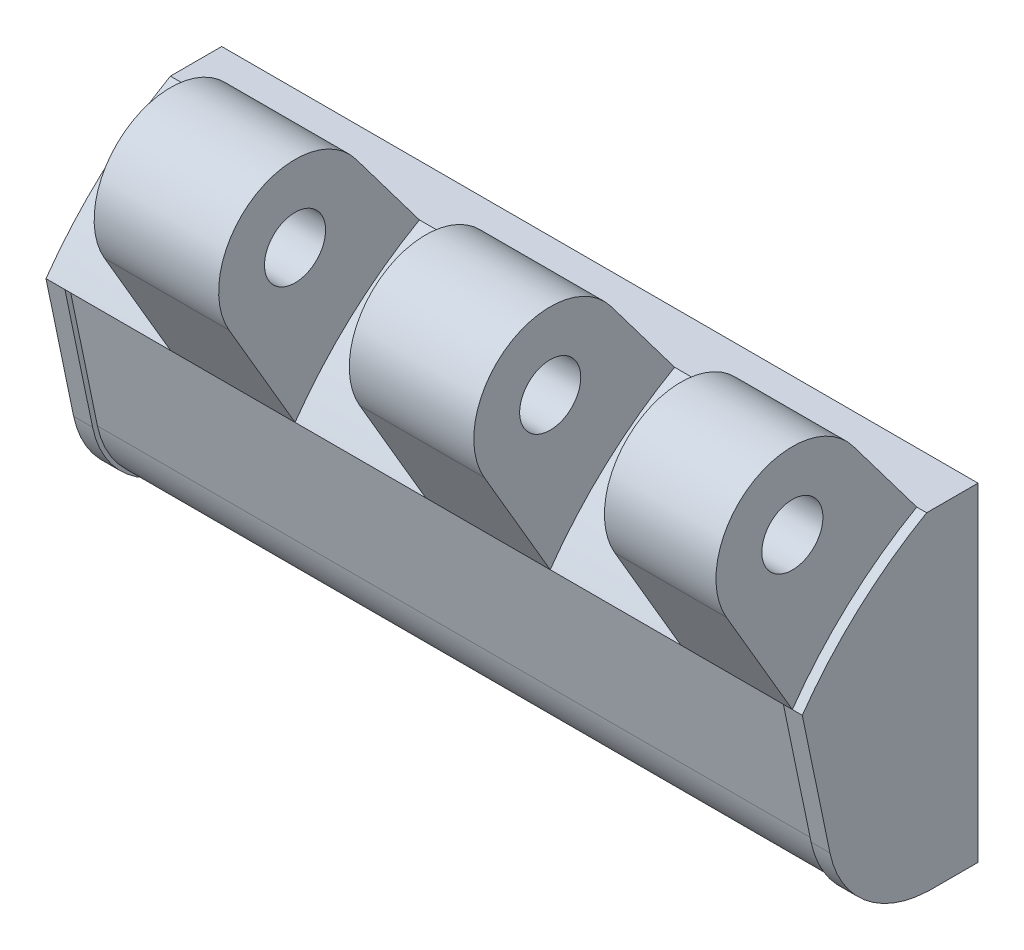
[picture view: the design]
ISO-10303-21;
HEADER;
FILE_DESCRIPTION(('STEP AP214'),'2;1');
FILE_NAME('part.step','',(''),(''),'','','');
FILE_SCHEMA(('AUTOMOTIVE_DESIGN { 1 0 10303 214 1 1 1 1 }'));
ENDSEC;
DATA;
#1=APPLICATION_CONTEXT('core data for automotive mechanical design processes');
#2=APPLICATION_PROTOCOL_DEFINITION('international standard','automotive_design',2000,#1);
#3=PRODUCT_CONTEXT('',#1,'mechanical');
#4=PRODUCT('Part','Part','',(#3));
#5=PRODUCT_RELATED_PRODUCT_CATEGORY('part','',(#4));
#6=PRODUCT_DEFINITION_FORMATION('','',#4);
#7=PRODUCT_DEFINITION_CONTEXT('part definition',#1,'design');
#8=PRODUCT_DEFINITION('design','',#6,#7);
#9=PRODUCT_DEFINITION_SHAPE('','',#8);
#10=(LENGTH_UNIT() NAMED_UNIT(*) SI_UNIT(.MILLI.,.METRE.));
#11=(NAMED_UNIT(*) PLANE_ANGLE_UNIT() SI_UNIT($,.RADIAN.));
#12=(NAMED_UNIT(*) SI_UNIT($,.STERADIAN.) SOLID_ANGLE_UNIT());
#13=UNCERTAINTY_MEASURE_WITH_UNIT(LENGTH_MEASURE(1.E-05),#10,'distance_accuracy_value','');
#14=(GEOMETRIC_REPRESENTATION_CONTEXT(3) GLOBAL_UNCERTAINTY_ASSIGNED_CONTEXT((#13)) GLOBAL_UNIT_ASSIGNED_CONTEXT((#10,
#11,#12)) REPRESENTATION_CONTEXT('',''));
#15=CARTESIAN_POINT('',(0.,0.,0.));
#16=DIRECTION('',(0.,0.,1.));
#17=DIRECTION('',(1.,0.,0.));
#18=AXIS2_PLACEMENT_3D('',#15,#16,#17);
#19=CARTESIAN_POINT('',(38.63875,-1.75,3.09));
#20=DIRECTION('',(1.,0.,0.));
#21=DIRECTION('',(0.,1.,0.));
#22=AXIS2_PLACEMENT_3D('',#19,#20,#21);
#23=CYLINDRICAL_SURFACE('',#22,5.54);
#24=CARTESIAN_POINT('',(4.3913410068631,-2.87725983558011,8.51410225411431));
#25=CARTESIAN_POINT('',(4.30887743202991,-3.00312845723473,8.48795452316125));
#26=CARTESIAN_POINT('',(4.22140014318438,-3.12482517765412,8.45808342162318));
#27=CARTESIAN_POINT('',(4.03734328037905,-3.35924431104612,8.39251775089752));
#28=CARTESIAN_POINT('',(3.94077371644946,-3.47197634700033,8.35682955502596));
#29=CARTESIAN_POINT('',(3.73932955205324,-3.68805254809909,8.28120986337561));
#30=CARTESIAN_POINT('',(3.63445953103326,-3.79140182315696,8.24128070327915));
#31=CARTESIAN_POINT('',(3.41699922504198,-3.98850366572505,8.15873930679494));
#32=CARTESIAN_POINT('',(3.30440670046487,-4.08225342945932,8.11612629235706));
#33=CARTESIAN_POINT('',(3.07245935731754,-4.25954371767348,8.02998631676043));
#34=CARTESIAN_POINT('',(2.95313025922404,-4.34311967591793,7.98646318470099));
#35=CARTESIAN_POINT('',(2.70786156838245,-4.50013603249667,7.90003043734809));
#36=CARTESIAN_POINT('',(2.58192228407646,-4.57357690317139,7.85712079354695));
#37=CARTESIAN_POINT('',(2.19444831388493,-4.77829147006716,7.73183154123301));
#38=CARTESIAN_POINT('',(1.92312321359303,-4.8940599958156,7.65283807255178));
#39=CARTESIAN_POINT('',(1.51124760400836,-5.02966399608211,7.55522317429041));
#40=CARTESIAN_POINT('',(1.3786690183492,-5.06763921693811,7.52695454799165));
#41=CARTESIAN_POINT('',(1.10976726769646,-5.13322765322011,7.47714785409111));
#42=CARTESIAN_POINT('',(0.973446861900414,-5.16084829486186,7.45560496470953));
#43=CARTESIAN_POINT('',(0.698338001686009,-5.20520859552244,7.42058171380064));
#44=CARTESIAN_POINT('',(0.55955584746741,-5.22197279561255,7.40708317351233));
#45=CARTESIAN_POINT('',(0.280513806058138,-5.24436768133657,7.38897743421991));
#46=CARTESIAN_POINT('',(0.140254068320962,-5.24999948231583,7.38436934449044));
#47=CARTESIAN_POINT('',(-0.132891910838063,-5.25000049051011,7.38436751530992));
#48=CARTESIAN_POINT('',(-0.265778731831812,-5.24494537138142,7.38850279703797));
#49=CARTESIAN_POINT('',(-0.530289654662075,-5.22483376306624,7.40477641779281));
#50=CARTESIAN_POINT('',(-0.661913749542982,-5.20977721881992,7.41691480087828));
#51=CARTESIAN_POINT('',(-0.922970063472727,-5.16992139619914,7.44848369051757));
#52=CARTESIAN_POINT('',(-1.05239890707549,-5.14510832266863,7.46792452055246));
#53=CARTESIAN_POINT('',(-1.30802798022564,-5.08613719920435,7.51302620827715));
#54=CARTESIAN_POINT('',(-1.43422653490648,-5.05197440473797,7.53869022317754));
#55=CARTESIAN_POINT('',(-1.80432713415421,-4.93691666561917,7.62256199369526));
#56=CARTESIAN_POINT('',(-2.04262731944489,-4.84299524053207,7.68804908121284));
#57=CARTESIAN_POINT('',(-2.50094454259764,-4.62304696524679,7.82858523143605));
#58=CARTESIAN_POINT('',(-2.72094186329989,-4.49698607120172,7.9036443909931));
#59=CARTESIAN_POINT('',(-3.05158525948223,-4.2745245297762,8.02223198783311));
#60=CARTESIAN_POINT('',(-3.16911911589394,-4.18813745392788,8.06566603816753));
#61=CARTESIAN_POINT('',(-3.39697526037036,-4.00554332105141,8.15105458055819));
#62=CARTESIAN_POINT('',(-3.50729551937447,-3.9093335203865,8.19300865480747));
#63=CARTESIAN_POINT('',(-3.71980166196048,-3.70769125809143,8.27370641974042));
#64=CARTESIAN_POINT('',(-3.82200921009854,-3.60228505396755,8.31245867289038));
#65=CARTESIAN_POINT('',(-4.01788726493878,-3.38241417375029,8.38530113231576));
#66=CARTESIAN_POINT('',(-4.11156457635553,-3.26795685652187,8.41939506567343));
#67=CARTESIAN_POINT('',(-4.23369002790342,-3.1050637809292,8.46191680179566));
#68=CARTESIAN_POINT('',(-4.2661655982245,-3.06029424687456,8.4730195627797));
#69=CARTESIAN_POINT('',(-4.32976870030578,-2.96962395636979,8.49428380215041));
#70=CARTESIAN_POINT('',(-4.36089689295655,-2.923723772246,8.50444574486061));
#71=CARTESIAN_POINT('',(-4.39134100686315,-2.87725983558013,8.5141022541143));
#72=B_SPLINE_CURVE_WITH_KNOTS('',3,(#24,#25,#26,#27,#28,#29,#30,#31,#32,#33,#34,#35,#36,#37,#38,
#39,#40,#41,#42,#43,#44,#45,#46,#47,#48,#49,#50,#51,#52,#53,#54,#55,#56,#57,#58,#59,#60,#61,#62,
#63,#64,#65,#66,#67,#68,#69,#70,#71),.UNSPECIFIED.,.F.,.F.,(4,2,2,2,2,2,2,2,2,2,2,2,2,2,2,2,2,2,
2,2,2,2,2,4),(0.,0.457875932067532,0.915253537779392,1.37238053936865,1.82964067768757,
2.28525969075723,2.74085746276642,3.65152617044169,4.07341460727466,4.49499988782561,
4.91562881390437,5.33621559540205,5.73472511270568,6.13323682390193,6.5323140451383,
6.93159415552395,7.72139795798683,8.51204186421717,8.96820328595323,9.42449247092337,
9.8795190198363,10.334179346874,10.5033853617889,10.6725074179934),.UNSPECIFIED.);
#73=CARTESIAN_POINT('',(4.3913410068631,-2.8772598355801,8.51410225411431));
#74=VERTEX_POINT('',#73);
#75=CARTESIAN_POINT('',(-4.3913410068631,-2.8772598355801,8.51410225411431));
#76=VERTEX_POINT('',#75);
#77=EDGE_CURVE('E438',#74,#76,#72,.T.);
#78=ORIENTED_EDGE('',*,*,#77,.T.);
#79=DIRECTION('',(1.,0.,0.));
#80=VECTOR('',#79,1.);
#81=CARTESIAN_POINT('',(38.63875,-2.8772598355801,8.51410225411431));
#82=LINE('',#81,#80);
#83=EDGE_CURVE('E304',#74,#76,#82,.F.);
#84=ORIENTED_EDGE('',*,*,#83,.F.);
#85=EDGE_LOOP('',(#78,#84));
#86=FACE_BOUND('',#85,.T.);
#87=ADVANCED_FACE('F14',(#86),#23,.F.);
#88=CARTESIAN_POINT('',(38.63875,-2.8772598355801,8.51410225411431));
#89=DIRECTION('',(0.,0.203476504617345,-0.979079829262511));
#90=DIRECTION('',(0.,0.979079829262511,0.203476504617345));
#91=AXIS2_PLACEMENT_3D('',#88,#89,#90);
#92=PLANE('',#91);
#93=CARTESIAN_POINT('',(0.,0.,9.11206654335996));
#94=DIRECTION('',(0.,0.203476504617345,-0.979079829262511));
#95=DIRECTION('',(0.,-0.979079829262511,-0.203476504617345));
#96=AXIS2_PLACEMENT_3D('',#93,#94,#95);
#97=ELLIPSE('',#96,5.36217767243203,5.25);
#98=EDGE_CURVE('E445',#76,#74,#97,.T.);
#99=ORIENTED_EDGE('',*,*,#98,.T.);
#100=ORIENTED_EDGE('',*,*,#83,.T.);
#101=EDGE_LOOP('',(#99,#100));
#102=FACE_BOUND('',#101,.T.);
#103=ADVANCED_FACE('F16',(#102),#92,.T.);
#104=CARTESIAN_POINT('',(38.63875,-1.75,3.09));
#105=DIRECTION('',(1.,0.,0.));
#106=DIRECTION('',(0.,1.,0.));
#107=AXIS2_PLACEMENT_3D('',#104,#105,#106);
#108=CYLINDRICAL_SURFACE('',#107,5.54);
#109=CARTESIAN_POINT('',(34.8913410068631,-2.87725983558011,8.51410225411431));
#110=CARTESIAN_POINT('',(34.8088774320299,-3.00312845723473,8.48795452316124));
#111=CARTESIAN_POINT('',(34.7214001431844,-3.12482517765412,8.45808342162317));
#112=CARTESIAN_POINT('',(34.537343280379,-3.35924431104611,8.39251775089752));
#113=CARTESIAN_POINT('',(34.4407737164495,-3.47197634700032,8.35682955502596));
#114=CARTESIAN_POINT('',(34.2393295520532,-3.68805254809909,8.28120986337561));
#115=CARTESIAN_POINT('',(34.1344595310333,-3.79140182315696,8.24128070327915));
#116=CARTESIAN_POINT('',(33.916999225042,-3.98850366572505,8.15873930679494));
#117=CARTESIAN_POINT('',(33.8044067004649,-4.08225342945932,8.11612629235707));
#118=CARTESIAN_POINT('',(33.5724593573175,-4.25954371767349,8.02998631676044));
#119=CARTESIAN_POINT('',(33.453130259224,-4.34311967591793,7.98646318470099));
#120=CARTESIAN_POINT('',(33.2078615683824,-4.50013603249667,7.90003043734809));
#121=CARTESIAN_POINT('',(33.0819222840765,-4.57357690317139,7.85712079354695));
#122=CARTESIAN_POINT('',(32.6944483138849,-4.77829147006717,7.73183154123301));
#123=CARTESIAN_POINT('',(32.423123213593,-4.8940599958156,7.65283807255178));
#124=CARTESIAN_POINT('',(32.0112476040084,-5.02966399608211,7.55522317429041));
#125=CARTESIAN_POINT('',(31.8786690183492,-5.06763921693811,7.52695454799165));
#126=CARTESIAN_POINT('',(31.6097672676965,-5.1332276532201,7.47714785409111));
#127=CARTESIAN_POINT('',(31.4734468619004,-5.16084829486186,7.45560496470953));
#128=CARTESIAN_POINT('',(31.198338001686,-5.20520859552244,7.42058171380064));
#129=CARTESIAN_POINT('',(31.0595558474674,-5.22197279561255,7.40708317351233));
#130=CARTESIAN_POINT('',(30.7805138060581,-5.24436768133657,7.38897743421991));
#131=CARTESIAN_POINT('',(30.640254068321,-5.24999948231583,7.38436934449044));
#132=CARTESIAN_POINT('',(30.3671080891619,-5.25000049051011,7.38436751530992));
#133=CARTESIAN_POINT('',(30.2342212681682,-5.24494537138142,7.38850279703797));
#134=CARTESIAN_POINT('',(29.9697103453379,-5.22483376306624,7.40477641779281));
#135=CARTESIAN_POINT('',(29.838086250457,-5.20977721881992,7.41691480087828));
#136=CARTESIAN_POINT('',(29.5770299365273,-5.16992139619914,7.44848369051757));
#137=CARTESIAN_POINT('',(29.4476010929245,-5.14510832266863,7.46792452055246));
#138=CARTESIAN_POINT('',(29.1919720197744,-5.08613719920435,7.51302620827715));
#139=CARTESIAN_POINT('',(29.0657734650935,-5.05197440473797,7.53869022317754));
#140=CARTESIAN_POINT('',(28.6956728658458,-4.93691666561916,7.62256199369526));
#141=CARTESIAN_POINT('',(28.4573726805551,-4.84299524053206,7.68804908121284));
#142=CARTESIAN_POINT('',(27.9990554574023,-4.62304696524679,7.82858523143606));
#143=CARTESIAN_POINT('',(27.7790581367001,-4.49698607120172,7.90364439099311));
#144=CARTESIAN_POINT('',(27.4484147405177,-4.27452452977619,8.02223198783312));
#145=CARTESIAN_POINT('',(27.330880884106,-4.18813745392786,8.06566603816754));
#146=CARTESIAN_POINT('',(27.1030247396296,-4.00554332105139,8.15105458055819));
#147=CARTESIAN_POINT('',(26.9927044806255,-3.90933352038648,8.19300865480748));
#148=CARTESIAN_POINT('',(26.7801983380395,-3.70769125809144,8.27370641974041));
#149=CARTESIAN_POINT('',(26.6779907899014,-3.60228505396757,8.31245867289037));
#150=CARTESIAN_POINT('',(26.4821127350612,-3.3824141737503,8.38530113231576));
#151=CARTESIAN_POINT('',(26.3884354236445,-3.26795685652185,8.41939506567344));
#152=CARTESIAN_POINT('',(26.2663099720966,-3.1050637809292,8.46191680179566));
#153=CARTESIAN_POINT('',(26.2338344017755,-3.06029424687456,8.4730195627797));
#154=CARTESIAN_POINT('',(26.1702312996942,-2.96962395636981,8.4942838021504));
#155=CARTESIAN_POINT('',(26.1391031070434,-2.92372377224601,8.50444574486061));
#156=CARTESIAN_POINT('',(26.1086589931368,-2.87725983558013,8.5141022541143));
#157=B_SPLINE_CURVE_WITH_KNOTS('',3,(#109,#110,#111,#112,#113,#114,#115,#116,#117,#118,#119,
#120,#121,#122,#123,#124,#125,#126,#127,#128,#129,#130,#131,#132,#133,#134,#135,#136,#137,#138,
#139,#140,#141,#142,#143,#144,#145,#146,#147,#148,#149,#150,#151,#152,#153,#154,#155,#156),
.UNSPECIFIED.,.F.,.F.,(4,2,2,2,2,2,2,2,2,2,2,2,2,2,2,2,2,2,2,2,2,2,2,4),(0.,0.457875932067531,
0.915253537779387,1.37238053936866,1.82964067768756,2.28525969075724,2.74085746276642,
3.65152617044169,4.07341460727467,4.49499988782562,4.91562881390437,5.33621559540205,
5.73472511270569,6.13323682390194,6.53231404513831,6.93159415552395,7.72139795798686,
8.51204186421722,8.96820328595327,9.42449247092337,9.87951901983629,10.334179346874,
10.5033853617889,10.6725074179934),.UNSPECIFIED.);
#158=CARTESIAN_POINT('',(34.8913410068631,-2.8772598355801,8.51410225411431));
#159=VERTEX_POINT('',#158);
#160=CARTESIAN_POINT('',(26.1086589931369,-2.8772598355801,8.51410225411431));
#161=VERTEX_POINT('',#160);
#162=EDGE_CURVE('E409',#159,#161,#157,.T.);
#163=ORIENTED_EDGE('',*,*,#162,.T.);
#164=DIRECTION('',(1.,0.,0.));
#165=VECTOR('',#164,1.);
#166=CARTESIAN_POINT('',(38.63875,-2.8772598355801,8.51410225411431));
#167=LINE('',#166,#165);
#168=EDGE_CURVE('E301',#159,#161,#167,.F.);
#169=ORIENTED_EDGE('',*,*,#168,.F.);
#170=EDGE_LOOP('',(#163,#169));
#171=FACE_BOUND('',#170,.T.);
#172=ADVANCED_FACE('F424',(#171),#108,.F.);
#173=CARTESIAN_POINT('',(38.63875,-2.8772598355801,8.51410225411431));
#174=DIRECTION('',(0.,0.203476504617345,-0.979079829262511));
#175=DIRECTION('',(0.,0.979079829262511,0.203476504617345));
#176=AXIS2_PLACEMENT_3D('',#173,#174,#175);
#177=PLANE('',#176);
#178=CARTESIAN_POINT('',(30.5,0.,9.11206654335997));
#179=DIRECTION('',(0.,0.203476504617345,-0.979079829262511));
#180=DIRECTION('',(0.,-0.979079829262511,-0.203476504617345));
#181=AXIS2_PLACEMENT_3D('',#178,#179,#180);
#182=ELLIPSE('',#181,5.36217767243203,5.25);
#183=EDGE_CURVE('E418',#161,#159,#182,.T.);
#184=ORIENTED_EDGE('',*,*,#183,.T.);
#185=ORIENTED_EDGE('',*,*,#168,.T.);
#186=EDGE_LOOP('',(#184,#185));
#187=FACE_BOUND('',#186,.T.);
#188=ADVANCED_FACE('F429',(#187),#177,.T.);
#189=CARTESIAN_POINT('',(0.,0.,7.675));
#190=DIRECTION('',(0.,0.,-1.));
#191=DIRECTION('',(-1.,0.,0.));
#192=AXIS2_PLACEMENT_3D('',#189,#190,#191);
#193=CYLINDRICAL_SURFACE('',#192,5.25);
#194=CARTESIAN_POINT('',(0.,0.,4.99999999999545));
#195=DIRECTION('',(0.,0.,1.));
#196=DIRECTION('',(0.,1.,0.));
#197=AXIS2_PLACEMENT_3D('',#194,#195,#196);
#198=CIRCLE('',#197,5.24999999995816);
#199=CARTESIAN_POINT('',(0.,5.24999999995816,4.99999999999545));
#200=VERTEX_POINT('',#199);
#201=EDGE_CURVE('E821',#200,#200,#198,.F.);
#202=ORIENTED_EDGE('',*,*,#201,.T.);
#203=EDGE_LOOP('',(#202));
#204=FACE_BOUND('',#203,.T.);
#205=ORIENTED_EDGE('',*,*,#98,.F.);
#206=ORIENTED_EDGE('',*,*,#77,.F.);
#207=EDGE_LOOP('',(#205,#206));
#208=FACE_BOUND('',#207,.T.);
#209=ADVANCED_FACE('F433',(#204,#208),#193,.F.);
#210=CARTESIAN_POINT('',(30.5,0.,7.675));
#211=DIRECTION('',(0.,0.,-1.));
#212=DIRECTION('',(-1.,0.,0.));
#213=AXIS2_PLACEMENT_3D('',#210,#211,#212);
#214=CYLINDRICAL_SURFACE('',#213,5.25);
#215=CARTESIAN_POINT('',(30.5,0.,4.99999999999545));
#216=DIRECTION('',(0.,0.,1.));
#217=DIRECTION('',(0.,1.,0.));
#218=AXIS2_PLACEMENT_3D('',#215,#216,#217);
#219=CIRCLE('',#218,5.24999999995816);
#220=CARTESIAN_POINT('',(30.5,5.24999999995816,4.99999999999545));
#221=VERTEX_POINT('',#220);
#222=EDGE_CURVE('E804',#221,#221,#219,.F.);
#223=ORIENTED_EDGE('',*,*,#222,.T.);
#224=EDGE_LOOP('',(#223));
#225=FACE_BOUND('',#224,.T.);
#226=ORIENTED_EDGE('',*,*,#183,.F.);
#227=ORIENTED_EDGE('',*,*,#162,.F.);
#228=EDGE_LOOP('',(#226,#227));
#229=FACE_BOUND('',#228,.T.);
#230=ADVANCED_FACE('F420',(#225,#229),#214,.F.);
#231=CARTESIAN_POINT('',(0.,0.,4.99999999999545));
#232=DIRECTION('',(0.,0.,1.));
#233=DIRECTION('',(1.,0.,0.));
#234=AXIS2_PLACEMENT_3D('',#231,#232,#233);
#235=CONICAL_SURFACE('',#234,5.24999999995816,0.896055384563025);
#236=CARTESIAN_POINT('',(0.,0.,3.));
#237=DIRECTION('',(0.,0.,-1.));
#238=DIRECTION('',(-1.,0.,0.));
#239=AXIS2_PLACEMENT_3D('',#236,#237,#238);
#240=CIRCLE('',#239,2.75);
#241=CARTESIAN_POINT('',(-2.75,0.,3.));
#242=VERTEX_POINT('',#241);
#243=EDGE_CURVE('E759',#242,#242,#240,.T.);
#244=ORIENTED_EDGE('',*,*,#243,.T.);
#245=EDGE_LOOP('',(#244));
#246=FACE_BOUND('',#245,.T.);
#247=ORIENTED_EDGE('',*,*,#201,.F.);
#248=EDGE_LOOP('',(#247));
#249=FACE_BOUND('',#248,.T.);
#250=ADVANCED_FACE('F546',(#246,#249),#235,.F.);
#251=CARTESIAN_POINT('',(30.5,0.,4.99999999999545));
#252=DIRECTION('',(0.,0.,1.));
#253=DIRECTION('',(1.,0.,0.));
#254=AXIS2_PLACEMENT_3D('',#251,#252,#253);
#255=CONICAL_SURFACE('',#254,5.24999999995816,0.896055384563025);
#256=CARTESIAN_POINT('',(30.5,0.,3.));
#257=DIRECTION('',(0.,0.,-1.));
#258=DIRECTION('',(-1.,0.,0.));
#259=AXIS2_PLACEMENT_3D('',#256,#257,#258);
#260=CIRCLE('',#259,2.75);
#261=CARTESIAN_POINT('',(27.75,0.,3.));
#262=VERTEX_POINT('',#261);
#263=EDGE_CURVE('E340',#262,#262,#260,.T.);
#264=ORIENTED_EDGE('',*,*,#263,.T.);
#265=EDGE_LOOP('',(#264));
#266=FACE_BOUND('',#265,.T.);
#267=ORIENTED_EDGE('',*,*,#222,.F.);
#268=EDGE_LOOP('',(#267));
#269=FACE_BOUND('',#268,.T.);
#270=ADVANCED_FACE('F549',(#266,#269),#255,.F.);
#271=CARTESIAN_POINT('',(0.,0.,1.5));
#272=DIRECTION('',(0.,0.,-1.));
#273=DIRECTION('',(-1.,0.,0.));
#274=AXIS2_PLACEMENT_3D('',#271,#272,#273);
#275=CYLINDRICAL_SURFACE('',#274,2.75);
#276=CARTESIAN_POINT('',(0.,0.,0.));
#277=DIRECTION('',(0.,0.,-1.));
#278=DIRECTION('',(-1.,0.,0.));
#279=AXIS2_PLACEMENT_3D('',#276,#277,#278);
#280=CIRCLE('',#279,2.75);
#281=CARTESIAN_POINT('',(-2.75,0.,0.));
#282=VERTEX_POINT('',#281);
#283=EDGE_CURVE('E320',#282,#282,#280,.F.);
#284=ORIENTED_EDGE('',*,*,#283,.F.);
#285=EDGE_LOOP('',(#284));
#286=FACE_BOUND('',#285,.T.);
#287=ORIENTED_EDGE('',*,*,#243,.F.);
#288=EDGE_LOOP('',(#287));
#289=FACE_BOUND('',#288,.T.);
#290=ADVANCED_FACE('F553',(#286,#289),#275,.F.);
#291=CARTESIAN_POINT('',(30.5,0.,1.5));
#292=DIRECTION('',(0.,0.,-1.));
#293=DIRECTION('',(-1.,0.,0.));
#294=AXIS2_PLACEMENT_3D('',#291,#292,#293);
#295=CYLINDRICAL_SURFACE('',#294,2.75);
#296=CARTESIAN_POINT('',(30.5,0.,0.));
#297=DIRECTION('',(0.,0.,-1.));
#298=DIRECTION('',(-1.,0.,0.));
#299=AXIS2_PLACEMENT_3D('',#296,#297,#298);
#300=CIRCLE('',#299,2.75);
#301=CARTESIAN_POINT('',(27.75,0.,0.));
#302=VERTEX_POINT('',#301);
#303=EDGE_CURVE('E316',#302,#302,#300,.F.);
#304=ORIENTED_EDGE('',*,*,#303,.F.);
#305=EDGE_LOOP('',(#304));
#306=FACE_BOUND('',#305,.T.);
#307=ORIENTED_EDGE('',*,*,#263,.F.);
#308=EDGE_LOOP('',(#307));
#309=FACE_BOUND('',#308,.T.);
#310=ADVANCED_FACE('F603',(#306,#309),#295,.F.);
#311=CARTESIAN_POINT('',(38.7625,-1.75,3.09));
#312=DIRECTION('',(1.,0.,0.));
#313=DIRECTION('',(0.,1.,0.));
#314=AXIS2_PLACEMENT_3D('',#311,#312,#313);
#315=CYLINDRICAL_SURFACE('',#314,5.54);
#316=CARTESIAN_POINT('',(-8.2625,-1.75,3.09));
#317=DIRECTION('',(1.,0.,0.));
#318=DIRECTION('',(0.,1.,0.));
#319=AXIS2_PLACEMENT_3D('',#316,#317,#318);
#320=CIRCLE('',#319,5.54);
#321=CARTESIAN_POINT('',(-8.2625,-7.28345498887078,3.35921345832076));
#322=VERTEX_POINT('',#321);
#323=CARTESIAN_POINT('',(-8.2625,-2.8772598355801,8.51410225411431));
#324=VERTEX_POINT('',#323);
#325=EDGE_CURVE('E406',#322,#324,#320,.F.);
#326=ORIENTED_EDGE('',*,*,#325,.F.);
#327=DIRECTION('',(1.,0.,0.));
#328=VECTOR('',#327,1.);
#329=CARTESIAN_POINT('',(38.7625,-7.28345498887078,3.35921345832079));
#330=LINE('',#329,#328);
#331=CARTESIAN_POINT('',(-8.13875,-7.28345498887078,3.35921345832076));
#332=VERTEX_POINT('',#331);
#333=EDGE_CURVE('E244',#322,#332,#330,.T.);
#334=ORIENTED_EDGE('',*,*,#333,.T.);
#335=CARTESIAN_POINT('',(-8.13875,-1.75,3.09));
#336=DIRECTION('',(1.,0.,0.));
#337=DIRECTION('',(0.,1.,0.));
#338=AXIS2_PLACEMENT_3D('',#335,#336,#337);
#339=CIRCLE('',#338,5.54);
#340=CARTESIAN_POINT('',(-8.13875,-2.8772598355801,8.51410225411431));
#341=VERTEX_POINT('',#340);
#342=EDGE_CURVE('E18',#332,#341,#339,.F.);
#343=ORIENTED_EDGE('',*,*,#342,.T.);
#344=DIRECTION('',(1.,0.,0.));
#345=VECTOR('',#344,1.);
#346=CARTESIAN_POINT('',(38.7625,-2.8772598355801,8.51410225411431));
#347=LINE('',#346,#345);
#348=EDGE_CURVE('E232',#341,#324,#347,.F.);
#349=ORIENTED_EDGE('',*,*,#348,.T.);
#350=EDGE_LOOP('',(#326,#334,#343,#349));
#351=FACE_BOUND('',#350,.T.);
#352=ADVANCED_FACE('F247',(#351),#315,.T.);
#353=CARTESIAN_POINT('',(38.7625,-1.75,3.09));
#354=DIRECTION('',(1.,0.,0.));
#355=DIRECTION('',(0.,1.,0.));
#356=AXIS2_PLACEMENT_3D('',#353,#354,#355);
#357=CYLINDRICAL_SURFACE('',#356,5.54);
#358=CARTESIAN_POINT('',(38.7625,-1.75,3.09));
#359=DIRECTION('',(1.,0.,0.));
#360=DIRECTION('',(0.,1.,0.));
#361=AXIS2_PLACEMENT_3D('',#358,#359,#360);
#362=CIRCLE('',#361,5.54);
#363=CARTESIAN_POINT('',(38.7625,-7.28345498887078,3.35921345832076));
#364=VERTEX_POINT('',#363);
#365=CARTESIAN_POINT('',(38.7625,-2.8772598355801,8.51410225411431));
#366=VERTEX_POINT('',#365);
#367=EDGE_CURVE('E385',#364,#366,#362,.F.);
#368=ORIENTED_EDGE('',*,*,#367,.T.);
#369=DIRECTION('',(1.,0.,0.));
#370=VECTOR('',#369,1.);
#371=CARTESIAN_POINT('',(38.7625,-2.8772598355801,8.51410225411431));
#372=LINE('',#371,#370);
#373=CARTESIAN_POINT('',(38.63875,-2.8772598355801,8.51410225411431));
#374=VERTEX_POINT('',#373);
#375=EDGE_CURVE('E253',#366,#374,#372,.F.);
#376=ORIENTED_EDGE('',*,*,#375,.T.);
#377=CARTESIAN_POINT('',(38.63875,-1.75,3.09));
#378=DIRECTION('',(1.,0.,0.));
#379=DIRECTION('',(0.,1.,0.));
#380=AXIS2_PLACEMENT_3D('',#377,#378,#379);
#381=CIRCLE('',#380,5.54);
#382=CARTESIAN_POINT('',(38.63875,-7.28345498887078,3.35921345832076));
#383=VERTEX_POINT('',#382);
#384=EDGE_CURVE('E826',#383,#374,#381,.F.);
#385=ORIENTED_EDGE('',*,*,#384,.F.);
#386=DIRECTION('',(1.,0.,0.));
#387=VECTOR('',#386,1.);
#388=CARTESIAN_POINT('',(38.7625,-7.28345498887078,3.35921345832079));
#389=LINE('',#388,#387);
#390=EDGE_CURVE('E256',#383,#364,#389,.T.);
#391=ORIENTED_EDGE('',*,*,#390,.T.);
#392=EDGE_LOOP('',(#368,#376,#385,#391));
#393=FACE_BOUND('',#392,.T.);
#394=ADVANCED_FACE('F467',(#393),#357,.T.);
#395=CARTESIAN_POINT('',(38.63875,-1.75,3.09));
#396=DIRECTION('',(1.,0.,0.));
#397=DIRECTION('',(0.,1.,0.));
#398=AXIS2_PLACEMENT_3D('',#395,#396,#397);
#399=CYLINDRICAL_SURFACE('',#398,6.54);
#400=CARTESIAN_POINT('',(38.63875,-1.75,3.09));
#401=DIRECTION('',(1.,0.,0.));
#402=DIRECTION('',(0.,1.,0.));
#403=AXIS2_PLACEMENT_3D('',#400,#401,#402);
#404=CIRCLE('',#403,6.54);
#405=CARTESIAN_POINT('',(38.63875,-8.28445668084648,3.35921345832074));
#406=VERTEX_POINT('',#405);
#407=CARTESIAN_POINT('',(38.63875,-3.08073634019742,9.49318208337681));
#408=VERTEX_POINT('',#407);
#409=EDGE_CURVE('E377',#406,#408,#404,.F.);
#410=ORIENTED_EDGE('',*,*,#409,.T.);
#411=DIRECTION('',(1.,0.,0.));
#412=VECTOR('',#411,1.);
#413=CARTESIAN_POINT('',(38.63875,-3.08073634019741,9.49318208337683));
#414=LINE('',#413,#412);
#415=CARTESIAN_POINT('',(-8.13875,-3.08073634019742,9.49318208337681));
#416=VERTEX_POINT('',#415);
#417=EDGE_CURVE('E380',#408,#416,#414,.F.);
#418=ORIENTED_EDGE('',*,*,#417,.T.);
#419=CARTESIAN_POINT('',(-8.13875,-1.75,3.09));
#420=DIRECTION('',(1.,0.,0.));
#421=DIRECTION('',(0.,1.,0.));
#422=AXIS2_PLACEMENT_3D('',#419,#420,#421);
#423=CIRCLE('',#422,6.54);
#424=CARTESIAN_POINT('',(-8.13875,-8.28445668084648,3.35921345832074));
#425=VERTEX_POINT('',#424);
#426=EDGE_CURVE('E381',#416,#425,#423,.T.);
#427=ORIENTED_EDGE('',*,*,#426,.T.);
#428=DIRECTION('',(1.,0.,0.));
#429=VECTOR('',#428,1.);
#430=CARTESIAN_POINT('',(40.,-8.2844566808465,3.35921345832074));
#431=LINE('',#430,#429);
#432=EDGE_CURVE('E678',#406,#425,#431,.F.);
#433=ORIENTED_EDGE('',*,*,#432,.F.);
#434=EDGE_LOOP('',(#410,#418,#427,#433));
#435=FACE_BOUND('',#434,.T.);
#436=ADVANCED_FACE('F470',(#435),#399,.T.);
#437=CARTESIAN_POINT('',(40.,-1.75,3.09));
#438=DIRECTION('',(1.,0.,0.));
#439=DIRECTION('',(0.,1.,0.));
#440=AXIS2_PLACEMENT_3D('',#437,#438,#439);
#441=CYLINDRICAL_SURFACE('',#440,6.74);
#442=CARTESIAN_POINT('',(-9.5,-1.75,3.09));
#443=DIRECTION('',(1.,0.,0.));
#444=DIRECTION('',(0.,1.,0.));
#445=AXIS2_PLACEMENT_3D('',#442,#443,#444);
#446=CIRCLE('',#445,6.74);
#447=CARTESIAN_POINT('',(-9.5,-3.12143164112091,9.68899804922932));
#448=VERTEX_POINT('',#447);
#449=CARTESIAN_POINT('',(-9.5,-8.48462130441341,3.35921345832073));
#450=VERTEX_POINT('',#449);
#451=EDGE_CURVE('E333',#448,#450,#446,.T.);
#452=ORIENTED_EDGE('',*,*,#451,.T.);
#453=DIRECTION('',(1.,0.,0.));
#454=VECTOR('',#453,1.);
#455=CARTESIAN_POINT('',(40.,-8.4846213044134,3.35921345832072));
#456=LINE('',#455,#454);
#457=CARTESIAN_POINT('',(-8.2625,-8.48462130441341,3.35921345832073));
#458=VERTEX_POINT('',#457);
#459=EDGE_CURVE('E679',#458,#450,#456,.F.);
#460=ORIENTED_EDGE('',*,*,#459,.F.);
#461=CARTESIAN_POINT('',(-8.2625,-1.75,3.09));
#462=DIRECTION('',(1.,0.,0.));
#463=DIRECTION('',(0.,1.,0.));
#464=AXIS2_PLACEMENT_3D('',#461,#462,#463);
#465=CIRCLE('',#464,6.74);
#466=CARTESIAN_POINT('',(-8.2625,-3.12143164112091,9.68899804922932));
#467=VERTEX_POINT('',#466);
#468=EDGE_CURVE('E373',#458,#467,#465,.F.);
#469=ORIENTED_EDGE('',*,*,#468,.T.);
#470=DIRECTION('',(1.,0.,0.));
#471=VECTOR('',#470,1.);
#472=CARTESIAN_POINT('',(40.,-3.1214316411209,9.68899804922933));
#473=LINE('',#472,#471);
#474=EDGE_CURVE('E372',#467,#448,#473,.F.);
#475=ORIENTED_EDGE('',*,*,#474,.T.);
#476=EDGE_LOOP('',(#452,#460,#469,#475));
#477=FACE_BOUND('',#476,.T.);
#478=ADVANCED_FACE('F544',(#477),#441,.T.);
#479=CARTESIAN_POINT('',(40.,-8.5,0.));
#480=DIRECTION('',(0.,0.,-1.));
#481=DIRECTION('',(-1.,0.,0.));
#482=AXIS2_PLACEMENT_3D('',#479,#480,#481);
#483=PLANE('',#482);
#484=DIRECTION('',(0.,1.,0.));
#485=VECTOR('',#484,1.);
#486=CARTESIAN_POINT('',(40.,-8.5,0.));
#487=LINE('',#486,#485);
#488=CARTESIAN_POINT('',(40.,13.,0.));
#489=VERTEX_POINT('',#488);
#490=CARTESIAN_POINT('',(40.,-8.5,0.));
#491=VERTEX_POINT('',#490);
#492=EDGE_CURVE('E24',#489,#491,#487,.F.);
#493=ORIENTED_EDGE('',*,*,#492,.T.);
#494=DIRECTION('',(-1.,0.,0.));
#495=VECTOR('',#494,1.);
#496=CARTESIAN_POINT('',(40.,-8.5,0.));
#497=LINE('',#496,#495);
#498=CARTESIAN_POINT('',(-9.5,-8.5,0.));
#499=VERTEX_POINT('',#498);
#500=EDGE_CURVE('E9',#491,#499,#497,.T.);
#501=ORIENTED_EDGE('',*,*,#500,.T.);
#502=DIRECTION('',(0.,1.,0.));
#503=VECTOR('',#502,1.);
#504=CARTESIAN_POINT('',(-9.5,-8.5,0.));
#505=LINE('',#504,#503);
#506=CARTESIAN_POINT('',(-9.5,13.,0.));
#507=VERTEX_POINT('',#506);
#508=EDGE_CURVE('E319',#499,#507,#505,.T.);
#509=ORIENTED_EDGE('',*,*,#508,.T.);
#510=DIRECTION('',(-1.,0.,0.));
#511=VECTOR('',#510,1.);
#512=CARTESIAN_POINT('',(40.,13.,0.));
#513=LINE('',#512,#511);
#514=EDGE_CURVE('E695',#507,#489,#513,.F.);
#515=ORIENTED_EDGE('',*,*,#514,.T.);
#516=EDGE_LOOP('',(#493,#501,#509,#515));
#517=FACE_BOUND('',#516,.T.);
#518=ORIENTED_EDGE('',*,*,#303,.T.);
#519=EDGE_LOOP('',(#518));
#520=FACE_BOUND('',#519,.T.);
#521=ORIENTED_EDGE('',*,*,#283,.T.);
#522=EDGE_LOOP('',(#521));
#523=FACE_BOUND('',#522,.T.);
#524=ADVANCED_FACE('F562',(#517,#520,#523),#483,.T.);
#525=CARTESIAN_POINT('',(40.,-8.5,3.35921345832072));
#526=DIRECTION('',(0.,-1.,0.));
#527=DIRECTION('',(1.,0.,0.));
#528=AXIS2_PLACEMENT_3D('',#525,#526,#527);
#529=PLANE('',#528);
#530=DIRECTION('',(0.,0.,1.));
#531=VECTOR('',#530,1.);
#532=CARTESIAN_POINT('',(40.,-8.5,3.35921345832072));
#533=LINE('',#532,#531);
#534=CARTESIAN_POINT('',(40.,-8.5,3.35921345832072));
#535=VERTEX_POINT('',#534);
#536=EDGE_CURVE('E33',#491,#535,#533,.T.);
#537=ORIENTED_EDGE('',*,*,#536,.T.);
#538=DIRECTION('',(1.,0.,0.));
#539=VECTOR('',#538,1.);
#540=CARTESIAN_POINT('',(40.,-8.5,3.35921345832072));
#541=LINE('',#540,#539);
#542=CARTESIAN_POINT('',(-9.5,-8.5,3.35921345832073));
#543=VERTEX_POINT('',#542);
#544=EDGE_CURVE('E323',#535,#543,#541,.F.);
#545=ORIENTED_EDGE('',*,*,#544,.T.);
#546=DIRECTION('',(0.,0.,1.));
#547=VECTOR('',#546,1.);
#548=CARTESIAN_POINT('',(-9.5,-8.5,3.35921345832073));
#549=LINE('',#548,#547);
#550=EDGE_CURVE('E660',#543,#499,#549,.F.);
#551=ORIENTED_EDGE('',*,*,#550,.T.);
#552=ORIENTED_EDGE('',*,*,#500,.F.);
#553=EDGE_LOOP('',(#537,#545,#551,#552));
#554=FACE_BOUND('',#553,.T.);
#555=ADVANCED_FACE('F600',(#554),#529,.T.);
#556=CARTESIAN_POINT('',(40.,-8.4846213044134,3.35921345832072));
#557=DIRECTION('',(0.,0.,1.));
#558=DIRECTION('',(0.,-1.,0.));
#559=AXIS2_PLACEMENT_3D('',#556,#557,#558);
#560=PLANE('',#559);
#561=DIRECTION('',(0.,1.,0.));
#562=VECTOR('',#561,1.);
#563=CARTESIAN_POINT('',(38.63875,15.5,3.35921345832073));
#564=LINE('',#563,#562);
#565=EDGE_CURVE('E249',#406,#383,#564,.T.);
#566=ORIENTED_EDGE('',*,*,#565,.F.);
#567=ORIENTED_EDGE('',*,*,#432,.T.);
#568=DIRECTION('',(0.,1.,0.));
#569=VECTOR('',#568,1.);
#570=CARTESIAN_POINT('',(-8.13875,15.5,3.35921345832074));
#571=LINE('',#570,#569);
#572=EDGE_CURVE('E226',#425,#332,#571,.T.);
#573=ORIENTED_EDGE('',*,*,#572,.T.);
#574=ORIENTED_EDGE('',*,*,#333,.F.);
#575=DIRECTION('',(0.,1.,0.));
#576=VECTOR('',#575,1.);
#577=CARTESIAN_POINT('',(-8.2625,15.5,3.35921345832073));
#578=LINE('',#577,#576);
#579=EDGE_CURVE('E408',#458,#322,#578,.T.);
#580=ORIENTED_EDGE('',*,*,#579,.F.);
#581=ORIENTED_EDGE('',*,*,#459,.T.);
#582=DIRECTION('',(0.,1.,0.));
#583=VECTOR('',#582,1.);
#584=CARTESIAN_POINT('',(-9.5,15.5,3.35921345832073));
#585=LINE('',#584,#583);
#586=EDGE_CURVE('E335',#450,#543,#585,.F.);
#587=ORIENTED_EDGE('',*,*,#586,.T.);
#588=ORIENTED_EDGE('',*,*,#544,.F.);
#589=DIRECTION('',(0.,1.,0.));
#590=VECTOR('',#589,1.);
#591=CARTESIAN_POINT('',(40.,15.5,3.35921345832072));
#592=LINE('',#591,#590);
#593=CARTESIAN_POINT('',(40.,-8.48462130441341,3.35921345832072));
#594=VERTEX_POINT('',#593);
#595=EDGE_CURVE('E327',#594,#535,#592,.F.);
#596=ORIENTED_EDGE('',*,*,#595,.F.);
#597=DIRECTION('',(1.,0.,0.));
#598=VECTOR('',#597,1.);
#599=CARTESIAN_POINT('',(40.,-8.4846213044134,3.35921345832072));
#600=LINE('',#599,#598);
#601=CARTESIAN_POINT('',(38.7625,-8.48462130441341,3.35921345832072));
#602=VERTEX_POINT('',#601);
#603=EDGE_CURVE('E675',#594,#602,#600,.F.);
#604=ORIENTED_EDGE('',*,*,#603,.T.);
#605=DIRECTION('',(0.,1.,0.));
#606=VECTOR('',#605,1.);
#607=CARTESIAN_POINT('',(38.7625,15.5,3.35921345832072));
#608=LINE('',#607,#606);
#609=EDGE_CURVE('E388',#602,#364,#608,.T.);
#610=ORIENTED_EDGE('',*,*,#609,.T.);
#611=ORIENTED_EDGE('',*,*,#390,.F.);
#612=EDGE_LOOP('',(#566,#567,#573,#574,#580,#581,#587,#588,#596,#604,#610,#611));
#613=FACE_BOUND('',#612,.T.);
#614=ADVANCED_FACE('F596',(#613),#560,.T.);
#615=CARTESIAN_POINT('',(40.,-1.75,3.09));
#616=DIRECTION('',(1.,0.,0.));
#617=DIRECTION('',(0.,1.,0.));
#618=AXIS2_PLACEMENT_3D('',#615,#616,#617);
#619=CYLINDRICAL_SURFACE('',#618,6.74);
#620=CARTESIAN_POINT('',(40.,-1.75,3.09));
#621=DIRECTION('',(1.,0.,0.));
#622=DIRECTION('',(0.,1.,0.));
#623=AXIS2_PLACEMENT_3D('',#620,#621,#622);
#624=CIRCLE('',#623,6.74);
#625=CARTESIAN_POINT('',(40.,-3.12143164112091,9.68899804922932));
#626=VERTEX_POINT('',#625);
#627=EDGE_CURVE('E324',#626,#594,#624,.T.);
#628=ORIENTED_EDGE('',*,*,#627,.F.);
#629=DIRECTION('',(1.,0.,0.));
#630=VECTOR('',#629,1.);
#631=CARTESIAN_POINT('',(40.,-3.1214316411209,9.68899804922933));
#632=LINE('',#631,#630);
#633=CARTESIAN_POINT('',(38.7625,-3.12143164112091,9.68899804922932));
#634=VERTEX_POINT('',#633);
#635=EDGE_CURVE('E344',#626,#634,#632,.F.);
#636=ORIENTED_EDGE('',*,*,#635,.T.);
#637=CARTESIAN_POINT('',(38.7625,-1.75,3.09));
#638=DIRECTION('',(1.,0.,0.));
#639=DIRECTION('',(0.,1.,0.));
#640=AXIS2_PLACEMENT_3D('',#637,#638,#639);
#641=CIRCLE('',#640,6.74);
#642=EDGE_CURVE('E341',#634,#602,#641,.T.);
#643=ORIENTED_EDGE('',*,*,#642,.T.);
#644=ORIENTED_EDGE('',*,*,#603,.F.);
#645=EDGE_LOOP('',(#628,#636,#643,#644));
#646=FACE_BOUND('',#645,.T.);
#647=ADVANCED_FACE('F462',(#646),#619,.T.);
#648=CARTESIAN_POINT('',(-8.13875,15.5,0.));
#649=DIRECTION('',(1.,0.,0.));
#650=DIRECTION('',(0.,1.,0.));
#651=AXIS2_PLACEMENT_3D('',#648,#649,#650);
#652=PLANE('',#651);
#653=ORIENTED_EDGE('',*,*,#572,.F.);
#654=ORIENTED_EDGE('',*,*,#426,.F.);
#655=DIRECTION('',(0.,-0.979079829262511,-0.203476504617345));
#656=VECTOR('',#655,1.);
#657=CARTESIAN_POINT('',(-8.13875,5.5926726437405,11.2957265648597));
#658=LINE('',#657,#656);
#659=CARTESIAN_POINT('',(-8.13875,5.5926726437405,11.2957265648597));
#660=VERTEX_POINT('',#659);
#661=EDGE_CURVE('E262',#660,#416,#658,.T.);
#662=ORIENTED_EDGE('',*,*,#661,.F.);
#663=DIRECTION('',(0.,0.,1.));
#664=VECTOR('',#663,1.);
#665=CARTESIAN_POINT('',(-8.13875,5.5926726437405,10.2743593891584));
#666=LINE('',#665,#664);
#667=CARTESIAN_POINT('',(-8.13875,5.5926726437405,10.2743593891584));
#668=VERTEX_POINT('',#667);
#669=EDGE_CURVE('E252',#660,#668,#666,.F.);
#670=ORIENTED_EDGE('',*,*,#669,.T.);
#671=DIRECTION('',(0.,0.979079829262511,0.203476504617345));
#672=VECTOR('',#671,1.);
#673=CARTESIAN_POINT('',(-8.13875,-2.8772598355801,8.51410225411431));
#674=LINE('',#673,#672);
#675=EDGE_CURVE('E236',#341,#668,#674,.T.);
#676=ORIENTED_EDGE('',*,*,#675,.F.);
#677=ORIENTED_EDGE('',*,*,#342,.F.);
#678=EDGE_LOOP('',(#653,#654,#662,#670,#676,#677));
#679=FACE_BOUND('',#678,.T.);
#680=ADVANCED_FACE('F250',(#679),#652,.F.);
#681=CARTESIAN_POINT('',(38.7625,-2.8772598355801,8.51410225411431));
#682=DIRECTION('',(0.,0.203476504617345,-0.979079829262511));
#683=DIRECTION('',(0.,0.979079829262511,0.203476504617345));
#684=AXIS2_PLACEMENT_3D('',#681,#682,#683);
#685=PLANE('',#684);
#686=DIRECTION('',(1.,0.,0.));
#687=VECTOR('',#686,1.);
#688=CARTESIAN_POINT('',(38.7625,5.5926726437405,10.2743593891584));
#689=LINE('',#688,#687);
#690=CARTESIAN_POINT('',(-8.2625,5.5926726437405,10.2743593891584));
#691=VERTEX_POINT('',#690);
#692=EDGE_CURVE('E243',#691,#668,#689,.T.);
#693=ORIENTED_EDGE('',*,*,#692,.F.);
#694=DIRECTION('',(0.,0.979079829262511,0.203476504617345));
#695=VECTOR('',#694,1.);
#696=CARTESIAN_POINT('',(-8.2625,-2.8772598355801,8.51410225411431));
#697=LINE('',#696,#695);
#698=EDGE_CURVE('E239',#324,#691,#697,.T.);
#699=ORIENTED_EDGE('',*,*,#698,.F.);
#700=ORIENTED_EDGE('',*,*,#348,.F.);
#701=ORIENTED_EDGE('',*,*,#675,.T.);
#702=EDGE_LOOP('',(#693,#699,#700,#701));
#703=FACE_BOUND('',#702,.T.);
#704=ADVANCED_FACE('F234',(#703),#685,.F.);
#705=CARTESIAN_POINT('',(-8.2625,15.5,0.));
#706=DIRECTION('',(1.,0.,0.));
#707=DIRECTION('',(0.,1.,0.));
#708=AXIS2_PLACEMENT_3D('',#705,#706,#707);
#709=PLANE('',#708);
#710=ORIENTED_EDGE('',*,*,#698,.T.);
#711=DIRECTION('',(0.,0.,1.));
#712=VECTOR('',#711,1.);
#713=CARTESIAN_POINT('',(-8.2625,5.5926726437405,10.2743593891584));
#714=LINE('',#713,#712);
#715=CARTESIAN_POINT('',(-8.2625,5.59267264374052,11.5));
#716=VERTEX_POINT('',#715);
#717=EDGE_CURVE('E781',#691,#716,#714,.T.);
#718=ORIENTED_EDGE('',*,*,#717,.T.);
#719=DIRECTION('',(0.,-0.979079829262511,-0.203476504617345));
#720=VECTOR('',#719,1.);
#721=CARTESIAN_POINT('',(-8.2625,5.59267264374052,11.5));
#722=LINE('',#721,#720);
#723=EDGE_CURVE('E376',#467,#716,#722,.F.);
#724=ORIENTED_EDGE('',*,*,#723,.F.);
#725=ORIENTED_EDGE('',*,*,#468,.F.);
#726=ORIENTED_EDGE('',*,*,#579,.T.);
#727=ORIENTED_EDGE('',*,*,#325,.T.);
#728=EDGE_LOOP('',(#710,#718,#724,#725,#726,#727));
#729=FACE_BOUND('',#728,.T.);
#730=ADVANCED_FACE('F490',(#729),#709,.T.);
#731=CARTESIAN_POINT('',(38.7625,15.5,0.));
#732=DIRECTION('',(1.,0.,0.));
#733=DIRECTION('',(0.,1.,0.));
#734=AXIS2_PLACEMENT_3D('',#731,#732,#733);
#735=PLANE('',#734);
#736=DIRECTION('',(0.,0.,1.));
#737=VECTOR('',#736,1.);
#738=CARTESIAN_POINT('',(38.7625,5.5926726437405,0.));
#739=LINE('',#738,#737);
#740=CARTESIAN_POINT('',(38.7625,5.5926726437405,10.2743593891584));
#741=VERTEX_POINT('',#740);
#742=CARTESIAN_POINT('',(38.7625,5.5926726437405,11.5));
#743=VERTEX_POINT('',#742);
#744=EDGE_CURVE('E384',#741,#743,#739,.T.);
#745=ORIENTED_EDGE('',*,*,#744,.F.);
#746=DIRECTION('',(0.,0.979079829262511,0.203476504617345));
#747=VECTOR('',#746,1.);
#748=CARTESIAN_POINT('',(38.7625,-2.8772598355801,8.51410225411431));
#749=LINE('',#748,#747);
#750=EDGE_CURVE('E387',#366,#741,#749,.T.);
#751=ORIENTED_EDGE('',*,*,#750,.F.);
#752=ORIENTED_EDGE('',*,*,#367,.F.);
#753=ORIENTED_EDGE('',*,*,#609,.F.);
#754=ORIENTED_EDGE('',*,*,#642,.F.);
#755=DIRECTION('',(0.,-0.979079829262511,-0.203476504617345));
#756=VECTOR('',#755,1.);
#757=CARTESIAN_POINT('',(38.7625,5.59267264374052,11.5));
#758=LINE('',#757,#756);
#759=EDGE_CURVE('E349',#743,#634,#758,.T.);
#760=ORIENTED_EDGE('',*,*,#759,.F.);
#761=EDGE_LOOP('',(#745,#751,#752,#753,#754,#760));
#762=FACE_BOUND('',#761,.T.);
#763=ADVANCED_FACE('F465',(#762),#735,.F.);
#764=CARTESIAN_POINT('',(38.7625,-2.8772598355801,8.51410225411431));
#765=DIRECTION('',(0.,0.203476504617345,-0.979079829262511));
#766=DIRECTION('',(0.,0.979079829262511,0.203476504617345));
#767=AXIS2_PLACEMENT_3D('',#764,#765,#766);
#768=PLANE('',#767);
#769=ORIENTED_EDGE('',*,*,#375,.F.);
#770=ORIENTED_EDGE('',*,*,#750,.T.);
#771=DIRECTION('',(-1.,0.,0.));
#772=VECTOR('',#771,1.);
#773=CARTESIAN_POINT('',(38.7625,5.5926726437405,10.2743593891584));
#774=LINE('',#773,#772);
#775=CARTESIAN_POINT('',(38.63875,5.5926726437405,10.2743593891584));
#776=VERTEX_POINT('',#775);
#777=EDGE_CURVE('E269',#741,#776,#774,.T.);
#778=ORIENTED_EDGE('',*,*,#777,.T.);
#779=DIRECTION('',(0.,0.979079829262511,0.203476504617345));
#780=VECTOR('',#779,1.);
#781=CARTESIAN_POINT('',(38.63875,-2.8772598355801,8.51410225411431));
#782=LINE('',#781,#780);
#783=EDGE_CURVE('E266',#374,#776,#782,.T.);
#784=ORIENTED_EDGE('',*,*,#783,.F.);
#785=EDGE_LOOP('',(#769,#770,#778,#784));
#786=FACE_BOUND('',#785,.T.);
#787=ADVANCED_FACE('F458',(#786),#768,.F.);
#788=CARTESIAN_POINT('',(38.63875,15.5,0.));
#789=DIRECTION('',(1.,0.,0.));
#790=DIRECTION('',(0.,1.,0.));
#791=AXIS2_PLACEMENT_3D('',#788,#789,#790);
#792=PLANE('',#791);
#793=DIRECTION('',(0.,-0.979079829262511,-0.203476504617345));
#794=VECTOR('',#793,1.);
#795=CARTESIAN_POINT('',(38.63875,5.5926726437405,11.2957265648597));
#796=LINE('',#795,#794);
#797=CARTESIAN_POINT('',(38.63875,5.5926726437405,11.2957265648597));
#798=VERTEX_POINT('',#797);
#799=EDGE_CURVE('E265',#408,#798,#796,.F.);
#800=ORIENTED_EDGE('',*,*,#799,.F.);
#801=ORIENTED_EDGE('',*,*,#409,.F.);
#802=ORIENTED_EDGE('',*,*,#565,.T.);
#803=ORIENTED_EDGE('',*,*,#384,.T.);
#804=ORIENTED_EDGE('',*,*,#783,.T.);
#805=DIRECTION('',(0.,0.,1.));
#806=VECTOR('',#805,1.);
#807=CARTESIAN_POINT('',(38.63875,5.5926726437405,10.2743593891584));
#808=LINE('',#807,#806);
#809=EDGE_CURVE('E271',#776,#798,#808,.T.);
#810=ORIENTED_EDGE('',*,*,#809,.T.);
#811=EDGE_LOOP('',(#800,#801,#802,#803,#804,#810));
#812=FACE_BOUND('',#811,.T.);
#813=ADVANCED_FACE('F454',(#812),#792,.T.);
#814=CARTESIAN_POINT('',(38.63875,5.5926726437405,11.2957265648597));
#815=DIRECTION('',(0.,-0.203476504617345,0.979079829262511));
#816=DIRECTION('',(0.,-0.979079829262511,-0.203476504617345));
#817=AXIS2_PLACEMENT_3D('',#814,#815,#816);
#818=PLANE('',#817);
#819=ORIENTED_EDGE('',*,*,#799,.T.);
#820=DIRECTION('',(-1.,0.,0.));
#821=VECTOR('',#820,1.);
#822=CARTESIAN_POINT('',(38.7625,5.5926726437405,11.2957265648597));
#823=LINE('',#822,#821);
#824=EDGE_CURVE('E286',#798,#660,#823,.T.);
#825=ORIENTED_EDGE('',*,*,#824,.T.);
#826=ORIENTED_EDGE('',*,*,#661,.T.);
#827=ORIENTED_EDGE('',*,*,#417,.F.);
#828=EDGE_LOOP('',(#819,#825,#826,#827));
#829=FACE_BOUND('',#828,.T.);
#830=ADVANCED_FACE('F450',(#829),#818,.T.);
#831=CARTESIAN_POINT('',(-9.5,15.5,0.));
#832=DIRECTION('',(1.,0.,0.));
#833=DIRECTION('',(0.,1.,0.));
#834=AXIS2_PLACEMENT_3D('',#831,#832,#833);
#835=PLANE('',#834);
#836=ORIENTED_EDGE('',*,*,#508,.F.);
#837=ORIENTED_EDGE('',*,*,#550,.F.);
#838=ORIENTED_EDGE('',*,*,#586,.F.);
#839=ORIENTED_EDGE('',*,*,#451,.F.);
#840=DIRECTION('',(0.,-0.979079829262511,-0.203476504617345));
#841=VECTOR('',#840,1.);
#842=CARTESIAN_POINT('',(-9.5,5.59267264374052,11.5));
#843=LINE('',#842,#841);
#844=CARTESIAN_POINT('',(-9.5,5.59267264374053,11.5));
#845=VERTEX_POINT('',#844);
#846=EDGE_CURVE('E336',#845,#448,#843,.T.);
#847=ORIENTED_EDGE('',*,*,#846,.F.);
#848=CARTESIAN_POINT('',(-9.5,-8.8700000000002,-9.1));
#849=DIRECTION('',(1.,0.,0.));
#850=DIRECTION('',(0.,1.,0.));
#851=AXIS2_PLACEMENT_3D('',#848,#849,#850);
#852=CIRCLE('',#851,25.17);
#853=CARTESIAN_POINT('',(-9.5,13.,3.35921345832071));
#854=VERTEX_POINT('',#853);
#855=EDGE_CURVE('E337',#854,#845,#852,.T.);
#856=ORIENTED_EDGE('',*,*,#855,.F.);
#857=DIRECTION('',(0.,0.,1.));
#858=VECTOR('',#857,1.);
#859=CARTESIAN_POINT('',(-9.5,13.,0.));
#860=LINE('',#859,#858);
#861=EDGE_CURVE('E671',#507,#854,#860,.T.);
#862=ORIENTED_EDGE('',*,*,#861,.F.);
#863=EDGE_LOOP('',(#836,#837,#838,#839,#847,#856,#862));
#864=FACE_BOUND('',#863,.T.);
#865=ADVANCED_FACE('F453',(#864),#835,.F.);
#866=CARTESIAN_POINT('',(40.,5.59267264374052,11.5));
#867=DIRECTION('',(0.,-0.203476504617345,0.979079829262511));
#868=DIRECTION('',(0.,-0.979079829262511,-0.203476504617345));
#869=AXIS2_PLACEMENT_3D('',#866,#867,#868);
#870=PLANE('',#869);
#871=ORIENTED_EDGE('',*,*,#846,.T.);
#872=ORIENTED_EDGE('',*,*,#474,.F.);
#873=ORIENTED_EDGE('',*,*,#723,.T.);
#874=DIRECTION('',(1.,0.,0.));
#875=VECTOR('',#874,1.);
#876=CARTESIAN_POINT('',(40.,5.59267264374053,11.5));
#877=LINE('',#876,#875);
#878=EDGE_CURVE('E371',#845,#716,#877,.T.);
#879=ORIENTED_EDGE('',*,*,#878,.F.);
#880=EDGE_LOOP('',(#871,#872,#873,#879));
#881=FACE_BOUND('',#880,.T.);
#882=ADVANCED_FACE('F555',(#881),#870,.T.);
#883=CARTESIAN_POINT('',(40.,13.,0.));
#884=DIRECTION('',(0.,1.,0.));
#885=DIRECTION('',(-1.,0.,0.));
#886=AXIS2_PLACEMENT_3D('',#883,#884,#885);
#887=PLANE('',#886);
#888=DIRECTION('',(0.,0.,1.));
#889=VECTOR('',#888,1.);
#890=CARTESIAN_POINT('',(40.,13.,0.));
#891=LINE('',#890,#889);
#892=CARTESIAN_POINT('',(40.,13.,3.3592134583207));
#893=VERTEX_POINT('',#892);
#894=EDGE_CURVE('E332',#489,#893,#891,.T.);
#895=ORIENTED_EDGE('',*,*,#894,.F.);
#896=ORIENTED_EDGE('',*,*,#514,.F.);
#897=ORIENTED_EDGE('',*,*,#861,.T.);
#898=DIRECTION('',(-1.,0.,0.));
#899=VECTOR('',#898,1.);
#900=CARTESIAN_POINT('',(40.,13.,3.35921345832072));
#901=LINE('',#900,#899);
#902=CARTESIAN_POINT('',(-1.35,13.,3.35921345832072));
#903=VERTEX_POINT('',#902);
#904=EDGE_CURVE('E727',#854,#903,#901,.F.);
#905=ORIENTED_EDGE('',*,*,#904,.T.);
#906=DIRECTION('',(-1.,0.,0.));
#907=VECTOR('',#906,1.);
#908=CARTESIAN_POINT('',(40.,13.,3.35921345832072));
#909=LINE('',#908,#907);
#910=CARTESIAN_POINT('',(6.8,13.,3.35921345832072));
#911=VERTEX_POINT('',#910);
#912=EDGE_CURVE('E724',#903,#911,#909,.F.);
#913=ORIENTED_EDGE('',*,*,#912,.T.);
#914=DIRECTION('',(-1.,0.,0.));
#915=VECTOR('',#914,1.);
#916=CARTESIAN_POINT('',(40.,13.,3.35921345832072));
#917=LINE('',#916,#915);
#918=CARTESIAN_POINT('',(15.35,13.,3.35921345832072));
#919=VERTEX_POINT('',#918);
#920=EDGE_CURVE('E716',#911,#919,#917,.F.);
#921=ORIENTED_EDGE('',*,*,#920,.T.);
#922=DIRECTION('',(-1.,0.,0.));
#923=VECTOR('',#922,1.);
#924=CARTESIAN_POINT('',(40.,13.,3.35921345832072));
#925=LINE('',#924,#923);
#926=CARTESIAN_POINT('',(23.5,13.,3.35921345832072));
#927=VERTEX_POINT('',#926);
#928=EDGE_CURVE('E713',#919,#927,#925,.F.);
#929=ORIENTED_EDGE('',*,*,#928,.T.);
#930=DIRECTION('',(-1.,0.,0.));
#931=VECTOR('',#930,1.);
#932=CARTESIAN_POINT('',(40.,13.,3.35921345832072));
#933=LINE('',#932,#931);
#934=CARTESIAN_POINT('',(32.05,13.,3.35921345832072));
#935=VERTEX_POINT('',#934);
#936=EDGE_CURVE('E704',#927,#935,#933,.F.);
#937=ORIENTED_EDGE('',*,*,#936,.T.);
#938=DIRECTION('',(-1.,0.,0.));
#939=VECTOR('',#938,1.);
#940=CARTESIAN_POINT('',(40.,13.,3.35921345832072));
#941=LINE('',#940,#939);
#942=CARTESIAN_POINT('',(39.35,13.,3.35921345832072));
#943=VERTEX_POINT('',#942);
#944=EDGE_CURVE('E692',#935,#943,#941,.F.);
#945=ORIENTED_EDGE('',*,*,#944,.T.);
#946=DIRECTION('',(-1.,0.,0.));
#947=VECTOR('',#946,1.);
#948=CARTESIAN_POINT('',(40.,13.,3.35921345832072));
#949=LINE('',#948,#947);
#950=EDGE_CURVE('E667',#943,#893,#949,.F.);
#951=ORIENTED_EDGE('',*,*,#950,.T.);
#952=EDGE_LOOP('',(#895,#896,#897,#905,#913,#921,#929,#937,#945,#951));
#953=FACE_BOUND('',#952,.T.);
#954=ADVANCED_FACE('F558',(#953),#887,.T.);
#955=CARTESIAN_POINT('',(40.,15.5,0.));
#956=DIRECTION('',(1.,0.,0.));
#957=DIRECTION('',(0.,1.,0.));
#958=AXIS2_PLACEMENT_3D('',#955,#956,#957);
#959=PLANE('',#958);
#960=ORIENTED_EDGE('',*,*,#595,.T.);
#961=ORIENTED_EDGE('',*,*,#536,.F.);
#962=ORIENTED_EDGE('',*,*,#492,.F.);
#963=ORIENTED_EDGE('',*,*,#894,.T.);
#964=CARTESIAN_POINT('',(40.,-8.8700000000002,-9.1));
#965=DIRECTION('',(1.,0.,0.));
#966=DIRECTION('',(0.,1.,0.));
#967=AXIS2_PLACEMENT_3D('',#964,#965,#966);
#968=CIRCLE('',#967,25.17);
#969=CARTESIAN_POINT('',(40.,5.59267264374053,11.5));
#970=VERTEX_POINT('',#969);
#971=EDGE_CURVE('E329',#893,#970,#968,.T.);
#972=ORIENTED_EDGE('',*,*,#971,.T.);
#973=DIRECTION('',(0.,-0.979079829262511,-0.203476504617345));
#974=VECTOR('',#973,1.);
#975=CARTESIAN_POINT('',(40.,5.59267264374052,11.5));
#976=LINE('',#975,#974);
#977=EDGE_CURVE('E328',#970,#626,#976,.T.);
#978=ORIENTED_EDGE('',*,*,#977,.T.);
#979=ORIENTED_EDGE('',*,*,#627,.T.);
#980=EDGE_LOOP('',(#960,#961,#962,#963,#972,#978,#979));
#981=FACE_BOUND('',#980,.T.);
#982=ADVANCED_FACE('F592',(#981),#959,.T.);
#983=CARTESIAN_POINT('',(40.,5.59267264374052,11.5));
#984=DIRECTION('',(0.,-0.203476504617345,0.979079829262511));
#985=DIRECTION('',(0.,-0.979079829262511,-0.203476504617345));
#986=AXIS2_PLACEMENT_3D('',#983,#984,#985);
#987=PLANE('',#986);
#988=DIRECTION('',(1.,0.,0.));
#989=VECTOR('',#988,1.);
#990=CARTESIAN_POINT('',(40.,5.59267264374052,11.5));
#991=LINE('',#990,#989);
#992=CARTESIAN_POINT('',(39.35,5.59267264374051,11.5));
#993=VERTEX_POINT('',#992);
#994=EDGE_CURVE('E345',#970,#993,#991,.F.);
#995=ORIENTED_EDGE('',*,*,#994,.T.);
#996=DIRECTION('',(1.,0.,0.));
#997=VECTOR('',#996,1.);
#998=CARTESIAN_POINT('',(32.05,5.5926726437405,11.5));
#999=LINE('',#998,#997);
#1000=EDGE_CURVE('E277',#743,#993,#999,.T.);
#1001=ORIENTED_EDGE('',*,*,#1000,.F.);
#1002=ORIENTED_EDGE('',*,*,#759,.T.);
#1003=ORIENTED_EDGE('',*,*,#635,.F.);
#1004=ORIENTED_EDGE('',*,*,#977,.F.);
#1005=EDGE_LOOP('',(#995,#1001,#1002,#1003,#1004));
#1006=FACE_BOUND('',#1005,.T.);
#1007=ADVANCED_FACE('F530',(#1006),#987,.T.);
#1008=CARTESIAN_POINT('',(38.7625,5.5926726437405,10.2743593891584));
#1009=DIRECTION('',(0.,1.,0.));
#1010=DIRECTION('',(-1.,0.,0.));
#1011=AXIS2_PLACEMENT_3D('',#1008,#1009,#1010);
#1012=PLANE('',#1011);
#1013=ORIENTED_EDGE('',*,*,#824,.F.);
#1014=ORIENTED_EDGE('',*,*,#809,.F.);
#1015=ORIENTED_EDGE('',*,*,#777,.F.);
#1016=ORIENTED_EDGE('',*,*,#744,.T.);
#1017=DIRECTION('',(-1.,0.,0.));
#1018=VECTOR('',#1017,1.);
#1019=CARTESIAN_POINT('',(38.7625,5.5926726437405,11.5));
#1020=LINE('',#1019,#1018);
#1021=CARTESIAN_POINT('',(32.05,5.59267264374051,11.5));
#1022=VERTEX_POINT('',#1021);
#1023=EDGE_CURVE('E272',#1022,#743,#1020,.F.);
#1024=ORIENTED_EDGE('',*,*,#1023,.F.);
#1025=DIRECTION('',(1.,0.,0.));
#1026=VECTOR('',#1025,1.);
#1027=CARTESIAN_POINT('',(40.,5.59267264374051,11.5));
#1028=LINE('',#1027,#1026);
#1029=CARTESIAN_POINT('',(23.5,5.59267264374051,11.5));
#1030=VERTEX_POINT('',#1029);
#1031=EDGE_CURVE('E354',#1030,#1022,#1028,.T.);
#1032=ORIENTED_EDGE('',*,*,#1031,.F.);
#1033=DIRECTION('',(-1.,0.,0.));
#1034=VECTOR('',#1033,1.);
#1035=CARTESIAN_POINT('',(38.7625,5.5926726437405,11.5));
#1036=LINE('',#1035,#1034);
#1037=CARTESIAN_POINT('',(15.35,5.59267264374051,11.5));
#1038=VERTEX_POINT('',#1037);
#1039=EDGE_CURVE('E784',#1038,#1030,#1036,.F.);
#1040=ORIENTED_EDGE('',*,*,#1039,.F.);
#1041=DIRECTION('',(1.,0.,0.));
#1042=VECTOR('',#1041,1.);
#1043=CARTESIAN_POINT('',(40.,5.59267264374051,11.5));
#1044=LINE('',#1043,#1042);
#1045=CARTESIAN_POINT('',(6.8,5.59267264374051,11.5));
#1046=VERTEX_POINT('',#1045);
#1047=EDGE_CURVE('E363',#1046,#1038,#1044,.T.);
#1048=ORIENTED_EDGE('',*,*,#1047,.F.);
#1049=DIRECTION('',(-1.,0.,0.));
#1050=VECTOR('',#1049,1.);
#1051=CARTESIAN_POINT('',(38.7625,5.5926726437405,11.5));
#1052=LINE('',#1051,#1050);
#1053=CARTESIAN_POINT('',(-1.35,5.59267264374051,11.5));
#1054=VERTEX_POINT('',#1053);
#1055=EDGE_CURVE('E786',#1054,#1046,#1052,.F.);
#1056=ORIENTED_EDGE('',*,*,#1055,.F.);
#1057=DIRECTION('',(1.,0.,0.));
#1058=VECTOR('',#1057,1.);
#1059=CARTESIAN_POINT('',(40.,5.59267264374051,11.5));
#1060=LINE('',#1059,#1058);
#1061=EDGE_CURVE('E734',#716,#1054,#1060,.T.);
#1062=ORIENTED_EDGE('',*,*,#1061,.F.);
#1063=ORIENTED_EDGE('',*,*,#717,.F.);
#1064=ORIENTED_EDGE('',*,*,#692,.T.);
#1065=ORIENTED_EDGE('',*,*,#669,.F.);
#1066=EDGE_LOOP('',(#1013,#1014,#1015,#1016,#1024,#1032,#1040,#1048,#1056,#1062,#1063,#1064,#1065));
#1067=FACE_BOUND('',#1066,.T.);
#1068=ADVANCED_FACE('F526',(#1067),#1012,.F.);
#1069=CARTESIAN_POINT('',(40.,-8.8700000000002,-9.1));
#1070=DIRECTION('',(1.,0.,0.));
#1071=DIRECTION('',(0.,1.,0.));
#1072=AXIS2_PLACEMENT_3D('',#1069,#1070,#1071);
#1073=CYLINDRICAL_SURFACE('',#1072,25.17);
#1074=ORIENTED_EDGE('',*,*,#878,.T.);
#1075=ORIENTED_EDGE('',*,*,#1061,.T.);
#1076=CARTESIAN_POINT('',(-1.35,-8.8700000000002,-9.1));
#1077=DIRECTION('',(1.,0.,0.));
#1078=DIRECTION('',(0.,1.,0.));
#1079=AXIS2_PLACEMENT_3D('',#1076,#1077,#1078);
#1080=CIRCLE('',#1079,25.17);
#1081=EDGE_CURVE('E368',#1054,#903,#1080,.F.);
#1082=ORIENTED_EDGE('',*,*,#1081,.T.);
#1083=ORIENTED_EDGE('',*,*,#904,.F.);
#1084=ORIENTED_EDGE('',*,*,#855,.T.);
#1085=EDGE_LOOP('',(#1074,#1075,#1082,#1083,#1084));
#1086=FACE_BOUND('',#1085,.T.);
#1087=ADVANCED_FACE('F529',(#1086),#1073,.T.);
#1088=CARTESIAN_POINT('',(6.8,13.,3.35921345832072));
#1089=DIRECTION('',(0.,0.601465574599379,-0.798898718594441));
#1090=DIRECTION('',(0.,0.798898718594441,0.601465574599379));
#1091=AXIS2_PLACEMENT_3D('',#1088,#1089,#1090);
#1092=PLANE('',#1091);
#1093=DIRECTION('',(0.,0.798898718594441,0.601465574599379));
#1094=VECTOR('',#1093,1.);
#1095=CARTESIAN_POINT('',(6.8,13.,3.35921345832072));
#1096=LINE('',#1095,#1094);
#1097=CARTESIAN_POINT('',(6.8,18.5073278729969,7.5055064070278));
#1098=VERTEX_POINT('',#1097);
#1099=EDGE_CURVE('E367',#1098,#911,#1096,.F.);
#1100=ORIENTED_EDGE('',*,*,#1099,.T.);
#1101=ORIENTED_EDGE('',*,*,#912,.F.);
#1102=DIRECTION('',(0.,0.798898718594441,0.601465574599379));
#1103=VECTOR('',#1102,1.);
#1104=CARTESIAN_POINT('',(-1.35,13.,3.35921345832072));
#1105=LINE('',#1104,#1103);
#1106=CARTESIAN_POINT('',(-1.35,18.5073278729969,7.5055064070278));
#1107=VERTEX_POINT('',#1106);
#1108=EDGE_CURVE('E731',#903,#1107,#1105,.T.);
#1109=ORIENTED_EDGE('',*,*,#1108,.T.);
#1110=DIRECTION('',(1.,0.,0.));
#1111=VECTOR('',#1110,1.);
#1112=CARTESIAN_POINT('',(6.8,18.5073278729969,7.5055064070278));
#1113=LINE('',#1112,#1111);
#1114=EDGE_CURVE('E730',#1107,#1098,#1113,.T.);
#1115=ORIENTED_EDGE('',*,*,#1114,.T.);
#1116=EDGE_LOOP('',(#1100,#1101,#1109,#1115));
#1117=FACE_BOUND('',#1116,.T.);
#1118=ADVANCED_FACE('F566',(#1117),#1092,.T.);
#1119=CARTESIAN_POINT('',(40.,-8.8700000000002,-9.1));
#1120=DIRECTION('',(1.,0.,0.));
#1121=DIRECTION('',(0.,1.,0.));
#1122=AXIS2_PLACEMENT_3D('',#1119,#1120,#1121);
#1123=CYLINDRICAL_SURFACE('',#1122,25.17);
#1124=CARTESIAN_POINT('',(15.35,-8.8700000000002,-9.1));
#1125=DIRECTION('',(1.,0.,0.));
#1126=DIRECTION('',(0.,1.,0.));
#1127=AXIS2_PLACEMENT_3D('',#1124,#1125,#1126);
#1128=CIRCLE('',#1127,25.17);
#1129=EDGE_CURVE('E359',#1038,#919,#1128,.F.);
#1130=ORIENTED_EDGE('',*,*,#1129,.T.);
#1131=ORIENTED_EDGE('',*,*,#920,.F.);
#1132=CARTESIAN_POINT('',(6.8,-8.8700000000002,-9.1));
#1133=DIRECTION('',(1.,0.,0.));
#1134=DIRECTION('',(0.,1.,0.));
#1135=AXIS2_PLACEMENT_3D('',#1132,#1133,#1134);
#1136=CIRCLE('',#1135,25.17);
#1137=EDGE_CURVE('E364',#911,#1046,#1136,.T.);
#1138=ORIENTED_EDGE('',*,*,#1137,.T.);
#1139=ORIENTED_EDGE('',*,*,#1047,.T.);
#1140=EDGE_LOOP('',(#1130,#1131,#1138,#1139));
#1141=FACE_BOUND('',#1140,.T.);
#1142=ADVANCED_FACE('F570',(#1141),#1123,.T.);
#1143=CARTESIAN_POINT('',(15.35,18.5073278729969,7.5055064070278));
#1144=DIRECTION('',(0.,0.601465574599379,-0.798898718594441));
#1145=DIRECTION('',(0.,0.798898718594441,0.601465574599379));
#1146=AXIS2_PLACEMENT_3D('',#1143,#1144,#1145);
#1147=PLANE('',#1146);
#1148=DIRECTION('',(0.,0.798898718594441,0.601465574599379));
#1149=VECTOR('',#1148,1.);
#1150=CARTESIAN_POINT('',(15.35,18.5073278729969,7.5055064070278));
#1151=LINE('',#1150,#1149);
#1152=CARTESIAN_POINT('',(15.35,18.5073278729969,7.5055064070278));
#1153=VERTEX_POINT('',#1152);
#1154=EDGE_CURVE('E719',#919,#1153,#1151,.T.);
#1155=ORIENTED_EDGE('',*,*,#1154,.T.);
#1156=DIRECTION('',(1.,0.,0.));
#1157=VECTOR('',#1156,1.);
#1158=CARTESIAN_POINT('',(15.35,18.5073278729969,7.5055064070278));
#1159=LINE('',#1158,#1157);
#1160=CARTESIAN_POINT('',(23.5,18.5073278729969,7.5055064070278));
#1161=VERTEX_POINT('',#1160);
#1162=EDGE_CURVE('E358',#1153,#1161,#1159,.T.);
#1163=ORIENTED_EDGE('',*,*,#1162,.T.);
#1164=DIRECTION('',(0.,0.798898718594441,0.601465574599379));
#1165=VECTOR('',#1164,1.);
#1166=CARTESIAN_POINT('',(23.5,18.5073278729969,7.5055064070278));
#1167=LINE('',#1166,#1165);
#1168=EDGE_CURVE('E362',#1161,#927,#1167,.F.);
#1169=ORIENTED_EDGE('',*,*,#1168,.T.);
#1170=ORIENTED_EDGE('',*,*,#928,.F.);
#1171=EDGE_LOOP('',(#1155,#1163,#1169,#1170));
#1172=FACE_BOUND('',#1171,.T.);
#1173=ADVANCED_FACE('F574',(#1172),#1147,.T.);
#1174=CARTESIAN_POINT('',(40.,-8.8700000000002,-9.1));
#1175=DIRECTION('',(1.,0.,0.));
#1176=DIRECTION('',(0.,1.,0.));
#1177=AXIS2_PLACEMENT_3D('',#1174,#1175,#1176);
#1178=CYLINDRICAL_SURFACE('',#1177,25.17);
#1179=CARTESIAN_POINT('',(23.5,-8.8700000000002,-9.1));
#1180=DIRECTION('',(1.,0.,0.));
#1181=DIRECTION('',(0.,1.,0.));
#1182=AXIS2_PLACEMENT_3D('',#1179,#1180,#1181);
#1183=CIRCLE('',#1182,25.17);
#1184=EDGE_CURVE('E351',#927,#1030,#1183,.T.);
#1185=ORIENTED_EDGE('',*,*,#1184,.T.);
#1186=ORIENTED_EDGE('',*,*,#1031,.T.);
#1187=CARTESIAN_POINT('',(32.05,-8.8700000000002,-9.1));
#1188=DIRECTION('',(1.,0.,0.));
#1189=DIRECTION('',(0.,1.,0.));
#1190=AXIS2_PLACEMENT_3D('',#1187,#1188,#1189);
#1191=CIRCLE('',#1190,25.17);
#1192=EDGE_CURVE('E355',#1022,#935,#1191,.F.);
#1193=ORIENTED_EDGE('',*,*,#1192,.T.);
#1194=ORIENTED_EDGE('',*,*,#936,.F.);
#1195=EDGE_LOOP('',(#1185,#1186,#1193,#1194));
#1196=FACE_BOUND('',#1195,.T.);
#1197=ADVANCED_FACE('F578',(#1196),#1178,.T.);
#1198=CARTESIAN_POINT('',(32.05,18.5073278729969,7.5055064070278));
#1199=DIRECTION('',(0.,0.601465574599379,-0.798898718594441));
#1200=DIRECTION('',(0.,0.798898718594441,0.601465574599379));
#1201=AXIS2_PLACEMENT_3D('',#1198,#1199,#1200);
#1202=PLANE('',#1201);
#1203=DIRECTION('',(0.,0.798898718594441,0.601465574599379));
#1204=VECTOR('',#1203,1.);
#1205=CARTESIAN_POINT('',(32.05,18.5073278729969,7.5055064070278));
#1206=LINE('',#1205,#1204);
#1207=CARTESIAN_POINT('',(32.05,18.5073278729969,7.5055064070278));
#1208=VERTEX_POINT('',#1207);
#1209=EDGE_CURVE('E708',#935,#1208,#1206,.T.);
#1210=ORIENTED_EDGE('',*,*,#1209,.T.);
#1211=DIRECTION('',(1.,0.,0.));
#1212=VECTOR('',#1211,1.);
#1213=CARTESIAN_POINT('',(32.05,18.5073278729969,7.5055064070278));
#1214=LINE('',#1213,#1212);
#1215=CARTESIAN_POINT('',(39.35,18.5073278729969,7.5055064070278));
#1216=VERTEX_POINT('',#1215);
#1217=EDGE_CURVE('E350',#1208,#1216,#1214,.T.);
#1218=ORIENTED_EDGE('',*,*,#1217,.T.);
#1219=DIRECTION('',(0.,0.798898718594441,0.601465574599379));
#1220=VECTOR('',#1219,1.);
#1221=CARTESIAN_POINT('',(39.35,18.5073278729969,7.5055064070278));
#1222=LINE('',#1221,#1220);
#1223=EDGE_CURVE('E705',#1216,#943,#1222,.F.);
#1224=ORIENTED_EDGE('',*,*,#1223,.T.);
#1225=ORIENTED_EDGE('',*,*,#944,.F.);
#1226=EDGE_LOOP('',(#1210,#1218,#1224,#1225));
#1227=FACE_BOUND('',#1226,.T.);
#1228=ADVANCED_FACE('F582',(#1227),#1202,.T.);
#1229=CARTESIAN_POINT('',(40.,-8.8700000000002,-9.1));
#1230=DIRECTION('',(1.,0.,0.));
#1231=DIRECTION('',(0.,1.,0.));
#1232=AXIS2_PLACEMENT_3D('',#1229,#1230,#1231);
#1233=CYLINDRICAL_SURFACE('',#1232,25.17);
#1234=ORIENTED_EDGE('',*,*,#971,.F.);
#1235=ORIENTED_EDGE('',*,*,#950,.F.);
#1236=CARTESIAN_POINT('',(39.35,-8.8700000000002,-9.1));
#1237=DIRECTION('',(1.,0.,0.));
#1238=DIRECTION('',(0.,1.,0.));
#1239=AXIS2_PLACEMENT_3D('',#1236,#1237,#1238);
#1240=CIRCLE('',#1239,25.17);
#1241=EDGE_CURVE('E346',#943,#993,#1240,.T.);
#1242=ORIENTED_EDGE('',*,*,#1241,.T.);
#1243=ORIENTED_EDGE('',*,*,#994,.F.);
#1244=EDGE_LOOP('',(#1234,#1235,#1242,#1243));
#1245=FACE_BOUND('',#1244,.T.);
#1246=ADVANCED_FACE('F476',(#1245),#1233,.T.);
#1247=CARTESIAN_POINT('',(32.05,5.5926726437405,11.5));
#1248=DIRECTION('',(0.,-0.504676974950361,0.863308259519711));
#1249=DIRECTION('',(0.,-0.863308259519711,-0.504676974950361));
#1250=AXIS2_PLACEMENT_3D('',#1247,#1248,#1249);
#1251=PLANE('',#1250);
#1252=ORIENTED_EDGE('',*,*,#1023,.T.);
#1253=ORIENTED_EDGE('',*,*,#1000,.T.);
#1254=DIRECTION('',(0.,-0.863308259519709,-0.504676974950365));
#1255=VECTOR('',#1254,1.);
#1256=CARTESIAN_POINT('',(39.35,12.9766151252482,15.8165412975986));
#1257=LINE('',#1256,#1255);
#1258=CARTESIAN_POINT('',(39.35,12.9766151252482,15.8165412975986));
#1259=VERTEX_POINT('',#1258);
#1260=EDGE_CURVE('E391',#1259,#993,#1257,.T.);
#1261=ORIENTED_EDGE('',*,*,#1260,.F.);
#1262=DIRECTION('',(-1.,0.,0.));
#1263=VECTOR('',#1262,1.);
#1264=CARTESIAN_POINT('',(32.05,12.9766151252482,15.8165412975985));
#1265=LINE('',#1264,#1263);
#1266=CARTESIAN_POINT('',(32.05,12.9766151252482,15.8165412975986));
#1267=VERTEX_POINT('',#1266);
#1268=EDGE_CURVE('E281',#1267,#1259,#1265,.F.);
#1269=ORIENTED_EDGE('',*,*,#1268,.F.);
#1270=DIRECTION('',(0.,-0.863308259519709,-0.504676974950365));
#1271=VECTOR('',#1270,1.);
#1272=CARTESIAN_POINT('',(32.05,12.9766151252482,15.8165412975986));
#1273=LINE('',#1272,#1271);
#1274=EDGE_CURVE('E313',#1267,#1022,#1273,.T.);
#1275=ORIENTED_EDGE('',*,*,#1274,.T.);
#1276=EDGE_LOOP('',(#1252,#1253,#1261,#1269,#1275));
#1277=FACE_BOUND('',#1276,.T.);
#1278=ADVANCED_FACE('F472',(#1277),#1251,.T.);
#1279=CARTESIAN_POINT('',(32.05,15.5,11.5));
#1280=DIRECTION('',(-1.,0.,0.));
#1281=DIRECTION('',(0.,-1.,0.));
#1282=AXIS2_PLACEMENT_3D('',#1279,#1280,#1281);
#1283=CYLINDRICAL_SURFACE('',#1282,5.);
#1284=CARTESIAN_POINT('',(32.05,15.5,11.5));
#1285=DIRECTION('',(-1.,0.,0.));
#1286=DIRECTION('',(0.,-1.,0.));
#1287=AXIS2_PLACEMENT_3D('',#1284,#1285,#1286);
#1288=CIRCLE('',#1287,5.);
#1289=EDGE_CURVE('E284',#1208,#1267,#1288,.F.);
#1290=ORIENTED_EDGE('',*,*,#1289,.T.);
#1291=ORIENTED_EDGE('',*,*,#1268,.T.);
#1292=CARTESIAN_POINT('',(39.35,15.5,11.5));
#1293=DIRECTION('',(-1.,0.,0.));
#1294=DIRECTION('',(0.,-1.,0.));
#1295=AXIS2_PLACEMENT_3D('',#1292,#1293,#1294);
#1296=CIRCLE('',#1295,5.);
#1297=EDGE_CURVE('E283',#1216,#1259,#1296,.F.);
#1298=ORIENTED_EDGE('',*,*,#1297,.F.);
#1299=ORIENTED_EDGE('',*,*,#1217,.F.);
#1300=EDGE_LOOP('',(#1290,#1291,#1298,#1299));
#1301=FACE_BOUND('',#1300,.T.);
#1302=ADVANCED_FACE('F475',(#1301),#1283,.T.);
#1303=CARTESIAN_POINT('',(39.35,15.5,0.));
#1304=DIRECTION('',(1.,0.,0.));
#1305=DIRECTION('',(0.,1.,0.));
#1306=AXIS2_PLACEMENT_3D('',#1303,#1304,#1305);
#1307=PLANE('',#1306);
#1308=ORIENTED_EDGE('',*,*,#1297,.T.);
#1309=ORIENTED_EDGE('',*,*,#1260,.T.);
#1310=ORIENTED_EDGE('',*,*,#1241,.F.);
#1311=ORIENTED_EDGE('',*,*,#1223,.F.);
#1312=EDGE_LOOP('',(#1308,#1309,#1310,#1311));
#1313=FACE_BOUND('',#1312,.T.);
#1314=CARTESIAN_POINT('',(39.35,15.5,11.5));
#1315=DIRECTION('',(1.,0.,0.));
#1316=DIRECTION('',(0.,0.,-1.));
#1317=AXIS2_PLACEMENT_3D('',#1314,#1315,#1316);
#1318=CIRCLE('',#1317,2.);
#1319=CARTESIAN_POINT('',(39.35,15.5,9.5));
#1320=VERTEX_POINT('',#1319);
#1321=EDGE_CURVE('E307',#1320,#1320,#1318,.T.);
#1322=ORIENTED_EDGE('',*,*,#1321,.F.);
#1323=EDGE_LOOP('',(#1322));
#1324=FACE_BOUND('',#1323,.T.);
#1325=ADVANCED_FACE('F534',(#1313,#1324),#1307,.T.);
#1326=CARTESIAN_POINT('',(32.05,15.5,0.));
#1327=DIRECTION('',(1.,0.,0.));
#1328=DIRECTION('',(0.,1.,0.));
#1329=AXIS2_PLACEMENT_3D('',#1326,#1327,#1328);
#1330=PLANE('',#1329);
#1331=CARTESIAN_POINT('',(32.05,15.5,11.5));
#1332=DIRECTION('',(1.,0.,0.));
#1333=DIRECTION('',(0.,0.,-1.));
#1334=AXIS2_PLACEMENT_3D('',#1331,#1332,#1333);
#1335=CIRCLE('',#1334,2.);
#1336=CARTESIAN_POINT('',(32.05,15.5,9.5));
#1337=VERTEX_POINT('',#1336);
#1338=EDGE_CURVE('E655',#1337,#1337,#1335,.T.);
#1339=ORIENTED_EDGE('',*,*,#1338,.T.);
#1340=EDGE_LOOP('',(#1339));
#1341=FACE_BOUND('',#1340,.T.);
#1342=ORIENTED_EDGE('',*,*,#1274,.F.);
#1343=ORIENTED_EDGE('',*,*,#1289,.F.);
#1344=ORIENTED_EDGE('',*,*,#1209,.F.);
#1345=ORIENTED_EDGE('',*,*,#1192,.F.);
#1346=EDGE_LOOP('',(#1342,#1343,#1344,#1345));
#1347=FACE_BOUND('',#1346,.T.);
#1348=ADVANCED_FACE('F482',(#1341,#1347),#1330,.F.);
#1349=CARTESIAN_POINT('',(15.35,5.5926726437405,11.5));
#1350=DIRECTION('',(0.,-0.504676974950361,0.863308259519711));
#1351=DIRECTION('',(0.,-0.863308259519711,-0.504676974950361));
#1352=AXIS2_PLACEMENT_3D('',#1349,#1350,#1351);
#1353=PLANE('',#1352);
#1354=DIRECTION('',(0.,-0.863308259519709,-0.504676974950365));
#1355=VECTOR('',#1354,1.);
#1356=CARTESIAN_POINT('',(15.35,12.9766151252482,15.8165412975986));
#1357=LINE('',#1356,#1355);
#1358=CARTESIAN_POINT('',(15.35,12.9766151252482,15.8165412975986));
#1359=VERTEX_POINT('',#1358);
#1360=EDGE_CURVE('E399',#1359,#1038,#1357,.T.);
#1361=ORIENTED_EDGE('',*,*,#1360,.T.);
#1362=ORIENTED_EDGE('',*,*,#1039,.T.);
#1363=DIRECTION('',(0.,-0.863308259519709,-0.504676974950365));
#1364=VECTOR('',#1363,1.);
#1365=CARTESIAN_POINT('',(23.5,12.9766151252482,15.8165412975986));
#1366=LINE('',#1365,#1364);
#1367=CARTESIAN_POINT('',(23.5,12.9766151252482,15.8165412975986));
#1368=VERTEX_POINT('',#1367);
#1369=EDGE_CURVE('E396',#1368,#1030,#1366,.T.);
#1370=ORIENTED_EDGE('',*,*,#1369,.F.);
#1371=DIRECTION('',(-1.,0.,0.));
#1372=VECTOR('',#1371,1.);
#1373=CARTESIAN_POINT('',(15.35,12.9766151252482,15.8165412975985));
#1374=LINE('',#1373,#1372);
#1375=EDGE_CURVE('E289',#1359,#1368,#1374,.F.);
#1376=ORIENTED_EDGE('',*,*,#1375,.F.);
#1377=EDGE_LOOP('',(#1361,#1362,#1370,#1376));
#1378=FACE_BOUND('',#1377,.T.);
#1379=ADVANCED_FACE('F478',(#1378),#1353,.T.);
#1380=CARTESIAN_POINT('',(15.35,15.5,11.5));
#1381=DIRECTION('',(-1.,0.,0.));
#1382=DIRECTION('',(0.,-1.,0.));
#1383=AXIS2_PLACEMENT_3D('',#1380,#1381,#1382);
#1384=CYLINDRICAL_SURFACE('',#1383,5.);
#1385=CARTESIAN_POINT('',(15.35,15.5,11.5));
#1386=DIRECTION('',(-1.,0.,0.));
#1387=DIRECTION('',(0.,-1.,0.));
#1388=AXIS2_PLACEMENT_3D('',#1385,#1386,#1387);
#1389=CIRCLE('',#1388,5.);
#1390=EDGE_CURVE('E292',#1153,#1359,#1389,.F.);
#1391=ORIENTED_EDGE('',*,*,#1390,.T.);
#1392=ORIENTED_EDGE('',*,*,#1375,.T.);
#1393=CARTESIAN_POINT('',(23.5,15.5,11.5));
#1394=DIRECTION('',(-1.,0.,0.));
#1395=DIRECTION('',(0.,-1.,0.));
#1396=AXIS2_PLACEMENT_3D('',#1393,#1394,#1395);
#1397=CIRCLE('',#1396,5.);
#1398=EDGE_CURVE('E291',#1161,#1368,#1397,.F.);
#1399=ORIENTED_EDGE('',*,*,#1398,.F.);
#1400=ORIENTED_EDGE('',*,*,#1162,.F.);
#1401=EDGE_LOOP('',(#1391,#1392,#1399,#1400));
#1402=FACE_BOUND('',#1401,.T.);
#1403=ADVANCED_FACE('F481',(#1402),#1384,.T.);
#1404=CARTESIAN_POINT('',(23.5,15.5,0.));
#1405=DIRECTION('',(1.,0.,0.));
#1406=DIRECTION('',(0.,1.,0.));
#1407=AXIS2_PLACEMENT_3D('',#1404,#1405,#1406);
#1408=PLANE('',#1407);
#1409=ORIENTED_EDGE('',*,*,#1398,.T.);
#1410=ORIENTED_EDGE('',*,*,#1369,.T.);
#1411=ORIENTED_EDGE('',*,*,#1184,.F.);
#1412=ORIENTED_EDGE('',*,*,#1168,.F.);
#1413=EDGE_LOOP('',(#1409,#1410,#1411,#1412));
#1414=FACE_BOUND('',#1413,.T.);
#1415=CARTESIAN_POINT('',(23.5,15.5,11.5));
#1416=DIRECTION('',(1.,0.,0.));
#1417=DIRECTION('',(0.,0.,-1.));
#1418=AXIS2_PLACEMENT_3D('',#1415,#1416,#1417);
#1419=CIRCLE('',#1418,2.);
#1420=CARTESIAN_POINT('',(23.5,15.5,9.5));
#1421=VERTEX_POINT('',#1420);
#1422=EDGE_CURVE('E652',#1421,#1421,#1419,.T.);
#1423=ORIENTED_EDGE('',*,*,#1422,.F.);
#1424=EDGE_LOOP('',(#1423));
#1425=FACE_BOUND('',#1424,.T.);
#1426=ADVANCED_FACE('F518',(#1414,#1425),#1408,.T.);
#1427=CARTESIAN_POINT('',(15.35,15.5,0.));
#1428=DIRECTION('',(1.,0.,0.));
#1429=DIRECTION('',(0.,1.,0.));
#1430=AXIS2_PLACEMENT_3D('',#1427,#1428,#1429);
#1431=PLANE('',#1430);
#1432=CARTESIAN_POINT('',(15.35,15.5,11.5));
#1433=DIRECTION('',(1.,0.,0.));
#1434=DIRECTION('',(0.,0.,-1.));
#1435=AXIS2_PLACEMENT_3D('',#1432,#1433,#1434);
#1436=CIRCLE('',#1435,2.);
#1437=CARTESIAN_POINT('',(15.35,15.5,9.5));
#1438=VERTEX_POINT('',#1437);
#1439=EDGE_CURVE('E647',#1438,#1438,#1436,.T.);
#1440=ORIENTED_EDGE('',*,*,#1439,.T.);
#1441=EDGE_LOOP('',(#1440));
#1442=FACE_BOUND('',#1441,.T.);
#1443=ORIENTED_EDGE('',*,*,#1360,.F.);
#1444=ORIENTED_EDGE('',*,*,#1390,.F.);
#1445=ORIENTED_EDGE('',*,*,#1154,.F.);
#1446=ORIENTED_EDGE('',*,*,#1129,.F.);
#1447=EDGE_LOOP('',(#1443,#1444,#1445,#1446));
#1448=FACE_BOUND('',#1447,.T.);
#1449=ADVANCED_FACE('F487',(#1442,#1448),#1431,.F.);
#1450=CARTESIAN_POINT('',(6.8,12.9766151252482,15.8165412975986));
#1451=DIRECTION('',(0.,-0.504676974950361,0.863308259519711));
#1452=DIRECTION('',(0.,-0.863308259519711,-0.504676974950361));
#1453=AXIS2_PLACEMENT_3D('',#1450,#1451,#1452);
#1454=PLANE('',#1453);
#1455=DIRECTION('',(0.,-0.863308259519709,-0.504676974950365));
#1456=VECTOR('',#1455,1.);
#1457=CARTESIAN_POINT('',(6.8,12.9766151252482,15.8165412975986));
#1458=LINE('',#1457,#1456);
#1459=CARTESIAN_POINT('',(6.8,12.9766151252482,15.8165412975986));
#1460=VERTEX_POINT('',#1459);
#1461=EDGE_CURVE('E402',#1460,#1046,#1458,.T.);
#1462=ORIENTED_EDGE('',*,*,#1461,.F.);
#1463=DIRECTION('',(1.,0.,0.));
#1464=VECTOR('',#1463,1.);
#1465=CARTESIAN_POINT('',(6.8,12.9766151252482,15.8165412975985));
#1466=LINE('',#1465,#1464);
#1467=CARTESIAN_POINT('',(-1.35,12.9766151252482,15.8165412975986));
#1468=VERTEX_POINT('',#1467);
#1469=EDGE_CURVE('E293',#1468,#1460,#1466,.T.);
#1470=ORIENTED_EDGE('',*,*,#1469,.F.);
#1471=DIRECTION('',(0.,-0.863308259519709,-0.504676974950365));
#1472=VECTOR('',#1471,1.);
#1473=CARTESIAN_POINT('',(-1.35,12.9766151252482,15.8165412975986));
#1474=LINE('',#1473,#1472);
#1475=EDGE_CURVE('E405',#1468,#1054,#1474,.T.);
#1476=ORIENTED_EDGE('',*,*,#1475,.T.);
#1477=ORIENTED_EDGE('',*,*,#1055,.T.);
#1478=EDGE_LOOP('',(#1462,#1470,#1476,#1477));
#1479=FACE_BOUND('',#1478,.T.);
#1480=ADVANCED_FACE('F484',(#1479),#1454,.T.);
#1481=CARTESIAN_POINT('',(6.8,15.5,11.5));
#1482=DIRECTION('',(1.,0.,0.));
#1483=DIRECTION('',(0.,1.,0.));
#1484=AXIS2_PLACEMENT_3D('',#1481,#1482,#1483);
#1485=CYLINDRICAL_SURFACE('',#1484,5.);
#1486=CARTESIAN_POINT('',(6.8,15.5,11.5));
#1487=DIRECTION('',(1.,0.,0.));
#1488=DIRECTION('',(0.,1.,0.));
#1489=AXIS2_PLACEMENT_3D('',#1486,#1487,#1488);
#1490=CIRCLE('',#1489,5.);
#1491=EDGE_CURVE('E294',#1098,#1460,#1490,.T.);
#1492=ORIENTED_EDGE('',*,*,#1491,.F.);
#1493=ORIENTED_EDGE('',*,*,#1114,.F.);
#1494=CARTESIAN_POINT('',(-1.35,15.5,11.5));
#1495=DIRECTION('',(1.,0.,0.));
#1496=DIRECTION('',(0.,1.,0.));
#1497=AXIS2_PLACEMENT_3D('',#1494,#1495,#1496);
#1498=CIRCLE('',#1497,5.);
#1499=EDGE_CURVE('E295',#1107,#1468,#1498,.T.);
#1500=ORIENTED_EDGE('',*,*,#1499,.T.);
#1501=ORIENTED_EDGE('',*,*,#1469,.T.);
#1502=EDGE_LOOP('',(#1492,#1493,#1500,#1501));
#1503=FACE_BOUND('',#1502,.T.);
#1504=ADVANCED_FACE('F486',(#1503),#1485,.T.);
#1505=CARTESIAN_POINT('',(6.8,15.5,0.));
#1506=DIRECTION('',(1.,0.,0.));
#1507=DIRECTION('',(0.,1.,0.));
#1508=AXIS2_PLACEMENT_3D('',#1505,#1506,#1507);
#1509=PLANE('',#1508);
#1510=CARTESIAN_POINT('',(6.8,15.5,11.5));
#1511=DIRECTION('',(1.,0.,0.));
#1512=DIRECTION('',(0.,0.,-1.));
#1513=AXIS2_PLACEMENT_3D('',#1510,#1511,#1512);
#1514=CIRCLE('',#1513,2.);
#1515=CARTESIAN_POINT('',(6.8,15.5,9.5));
#1516=VERTEX_POINT('',#1515);
#1517=EDGE_CURVE('E641',#1516,#1516,#1514,.T.);
#1518=ORIENTED_EDGE('',*,*,#1517,.F.);
#1519=EDGE_LOOP('',(#1518));
#1520=FACE_BOUND('',#1519,.T.);
#1521=ORIENTED_EDGE('',*,*,#1491,.T.);
#1522=ORIENTED_EDGE('',*,*,#1461,.T.);
#1523=ORIENTED_EDGE('',*,*,#1137,.F.);
#1524=ORIENTED_EDGE('',*,*,#1099,.F.);
#1525=EDGE_LOOP('',(#1521,#1522,#1523,#1524));
#1526=FACE_BOUND('',#1525,.T.);
#1527=ADVANCED_FACE('F508',(#1520,#1526),#1509,.T.);
#1528=CARTESIAN_POINT('',(-1.35,15.5,0.));
#1529=DIRECTION('',(1.,0.,0.));
#1530=DIRECTION('',(0.,1.,0.));
#1531=AXIS2_PLACEMENT_3D('',#1528,#1529,#1530);
#1532=PLANE('',#1531);
#1533=ORIENTED_EDGE('',*,*,#1475,.F.);
#1534=ORIENTED_EDGE('',*,*,#1499,.F.);
#1535=ORIENTED_EDGE('',*,*,#1108,.F.);
#1536=ORIENTED_EDGE('',*,*,#1081,.F.);
#1537=EDGE_LOOP('',(#1533,#1534,#1535,#1536));
#1538=FACE_BOUND('',#1537,.T.);
#1539=CARTESIAN_POINT('',(-1.35,15.5,11.5));
#1540=DIRECTION('',(1.,0.,0.));
#1541=DIRECTION('',(0.,0.,-1.));
#1542=AXIS2_PLACEMENT_3D('',#1539,#1540,#1541);
#1543=CIRCLE('',#1542,2.);
#1544=CARTESIAN_POINT('',(-1.35,15.5,9.5));
#1545=VERTEX_POINT('',#1544);
#1546=EDGE_CURVE('E644',#1545,#1545,#1543,.T.);
#1547=ORIENTED_EDGE('',*,*,#1546,.T.);
#1548=EDGE_LOOP('',(#1547));
#1549=FACE_BOUND('',#1548,.T.);
#1550=ADVANCED_FACE('F504',(#1538,#1549),#1532,.F.);
#1551=CARTESIAN_POINT('',(-9.50010307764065,15.5,11.5));
#1552=DIRECTION('',(1.,0.,0.));
#1553=DIRECTION('',(0.,1.,0.));
#1554=AXIS2_PLACEMENT_3D('',#1551,#1552,#1553);
#1555=CYLINDRICAL_SURFACE('',#1554,2.);
#1556=ORIENTED_EDGE('',*,*,#1517,.T.);
#1557=EDGE_LOOP('',(#1556));
#1558=FACE_BOUND('',#1557,.T.);
#1559=ORIENTED_EDGE('',*,*,#1546,.F.);
#1560=EDGE_LOOP('',(#1559));
#1561=FACE_BOUND('',#1560,.T.);
#1562=ADVANCED_FACE('F507',(#1558,#1561),#1555,.F.);
#1563=ORIENTED_EDGE('',*,*,#1422,.T.);
#1564=EDGE_LOOP('',(#1563));
#1565=FACE_BOUND('',#1564,.T.);
#1566=ORIENTED_EDGE('',*,*,#1439,.F.);
#1567=EDGE_LOOP('',(#1566));
#1568=FACE_BOUND('',#1567,.T.);
#1569=ADVANCED_FACE('F624',(#1565,#1568),#1555,.F.);
#1570=ORIENTED_EDGE('',*,*,#1321,.T.);
#1571=EDGE_LOOP('',(#1570));
#1572=FACE_BOUND('',#1571,.T.);
#1573=ORIENTED_EDGE('',*,*,#1338,.F.);
#1574=EDGE_LOOP('',(#1573));
#1575=FACE_BOUND('',#1574,.T.);
#1576=ADVANCED_FACE('F622',(#1572,#1575),#1555,.F.);
#1577=CLOSED_SHELL('',(#87,#103,#172,#188,#209,#230,#250,#270,#290,#310,#352,#394,#436,#478,
#524,#555,#614,#647,#680,#704,#730,#763,#787,#813,#830,#865,#882,#954,#982,#1007,#1068,#1087,
#1118,#1142,#1173,#1197,#1228,#1246,#1278,#1302,#1325,#1348,#1379,#1403,#1426,#1449,#1480,#1504,
#1527,#1550,#1562,#1569,#1576));
#1578=MANIFOLD_SOLID_BREP('B1',#1577);
#1579=ADVANCED_BREP_SHAPE_REPRESENTATION('',(#18,#1578),#14);
#1580=SHAPE_DEFINITION_REPRESENTATION(#9,#1579);
ENDSEC;
END-ISO-10303-21;
